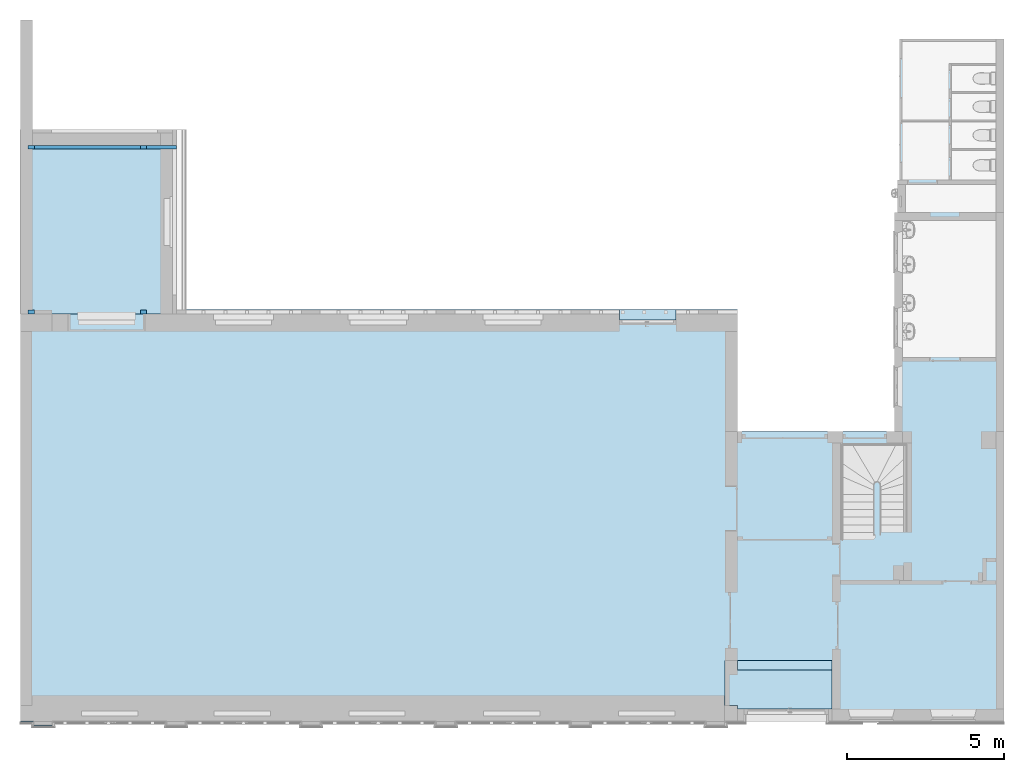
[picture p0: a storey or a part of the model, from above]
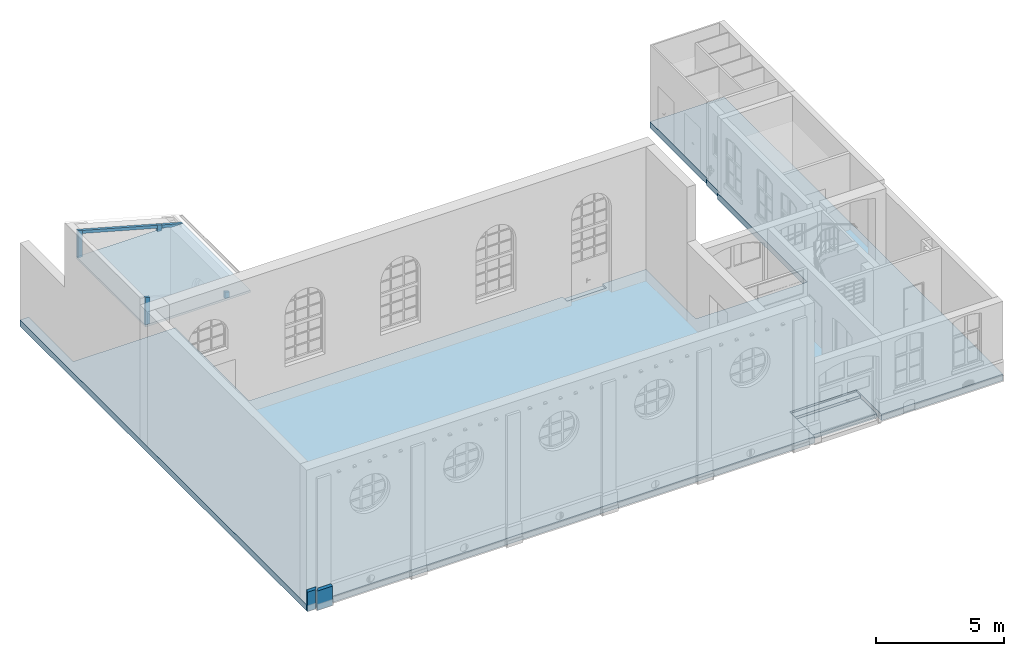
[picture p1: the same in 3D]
Properties of the parts of a building model (IFC4), part 1 of 2

# File
Description: no view
File name: KRD021.ifc
Time: 2026-01-22T15:29:08
Author: AP03
Organization: No Organization
Written by: ODA SDAI 25.4
Authorization: AP03

# IfcSite, Liegenschaft XXXXXXXXX (LuGM-Nr.) (TB 1-99) ANPASSEN !!!
RefLatitude: 48, 8, 10, 320000; RefLongitude: 11, 41, 19, 320000

# IfcBuildingStorey (25)
Name | In | Elevation (m)
Lageplan mit Gebäudebezeichnung und Geodaten (TB 20-24) |  | 0
Landschafts-/Freiflächenplanung (TB 25-29) |  | 0
Ver-/Entsorgungsleitungen mit geobasierten Daten (Daten an FB 62 übermitteln) (TB 30-39) |  | 0
Feuerwehrpläne (TB 40-49) |  | 0
Brandschutzpläne (TB 50-59) |  | 0
Nachrichten-/Netzwerktechnik (TB 60-69) |  | 0
Gefahrenmeldeanlagen (TB 70-79) |  | 0
Flucht-/Rettungswegpläne (TB 80-84) |  | 0
Geb. A Fundamentplan (TB 100-102) | Bestandsgebäude A - Sporthalle / Wohnhaus (TB 100-499) ANPASSEN !!! | 0
Geb. A 1. Untergeschoss (TB 150-199) | Bestandsgebäude A - Sporthalle / Wohnhaus (TB 100-499) ANPASSEN !!! | -2.4
Architektur (TB 150-159) | Geb. A 1. Untergeschoss (TB 150-199)
TGA (TB 160-194) | Geb. A 1. Untergeschoss (TB 150-199)
Brandschutz (TB 195-199) | Geb. A 1. Untergeschoss (TB 150-199)
Geb. A Erdgeschoss (TB 200-249) | Bestandsgebäude A - Sporthalle / Wohnhaus (TB 100-499) ANPASSEN !!! | 0
Architektur (TB 200-209) | Geb. A Erdgeschoss (TB 200-249)
TGA (TB 210-244) | Geb. A Erdgeschoss (TB 200-249)
Brandschutz (TB 245-249) | Geb. A Erdgeschoss (TB 200-249)
Geb. A 1. Obergeschoss (TB 250-299) | Bestandsgebäude A - Sporthalle / Wohnhaus (TB 100-499) ANPASSEN !!! | 3.87
Architektur (TB 250-259) | Geb. A 1. Obergeschoss (TB 250-299)
TGA (TB 260-294) | Geb. A 1. Obergeschoss (TB 250-299)
Brandschutz (TB 295-299) | Geb. A 1. Obergeschoss (TB 250-299)
Geb. A Dachgeschoss (TB 450-499) | Bestandsgebäude A - Sporthalle / Wohnhaus (TB 100-499) ANPASSEN !!! | 7.71
Architektur (TB 450-459) | Geb. A Dachgeschoss (TB 450-499)
TGA (TB 460-494) | Geb. A Dachgeschoss (TB 450-499)
Brandschutz (TB 495-499) | Geb. A Dachgeschoss (TB 450-499)

# IfcSpace (21)
LongName: EG
AllplanAttributes - Raumumschließung: R; Flächenart_DIN277: N; Flächenart_Wohnfläche: WO; BauNVO_Anrechnung_auf_GR: 0; Nutzungsart_Din277: USA; BauNVO_Anrechnung_auf_GF: 0; Raum unter Treppe (Wohnfl erst ab 2m): 0; Faktor_Wohnfläche_Raum: 1; Faktor_DIN277: 1; Abrechnungsart: m²; Objektname: Raum
Pset_SpaceCommon - IsExternal: no; HandicapAccessible: no; GrossPlannedArea: 0 m2; NetPlannedArea: 0 m2; PubliclyAccessible: yes
Name | In | Ortscode_Geschoßbezeichnung | Allright_Bauteil_ID
TURNHALLE | Architektur (TB 200-209) | E.02 | 0208Rau0000000012
GERÄTE-R. | Architektur (TB 200-209) | E.01 | 0208Rau0000000137
FLUR | Architektur (TB 200-209) | E.04 | 0208Rau0000000301
UMKLEIDE-R.3 | Architektur (TB 200-209) | E.03 | 0208Rau0000000314
UMKLEIDE-R.1 | Architektur (TB 200-209) | E.05 | 0208Rau0000000262
UMKLEIDE-R.2 | Architektur (TB 200-209) | E.07 | 0208Rau0000000239
WASCHR. | Architektur (TB 200-209) | E.08 | 0208Rau0000000150
ABSTELL-R. | Architektur (TB 200-209) | E.09 | 0208Rau0000000203
MÄDCHEN | Architektur (TB 200-209) | E.10 | 0208Rau0000000176
KNABEN | Architektur (TB 200-209) | E.11 | 0208Rau0000000163
TREPPEN | Architektur (TB 200-209) | E.06 | 0208Rau0000000252
TURNHALLE | Architektur (TB 250-259) | OG.01 | 0257Rau0000000002
FLUR | Architektur (TB 250-259) | OG.03 | 0257Rau0000000028
UMKLEIDE-R.3 | Architektur (TB 250-259) | OG.02 | 0257Rau0000000015
ZIMMER | Architektur (TB 250-259) | OG.07 | 0257Rau0000000093
UMKLEIDE-R.2 | Architektur (TB 250-259) | OG.06 | 0257Rau0000000054
UMKLEIDE-R.1 | Architektur (TB 250-259) | OG.04 | 0257Rau0000000041
TREPPEN | Architektur (TB 250-259) | OG.05 | 0257Rau0000000080
KAMMER | Architektur (TB 450-459) | D.03 | 0455Rau0000000026
TREPPEN | Architektur (TB 450-459) | D.02 | 0455Rau0000000023
TURNHALLE | Architektur (TB 450-459) | D.01 | 0455Rau0000000020

# IfcBeam (53)
Pset_BeamCommon - Status: NEW
Name | In | PredefinedType | Schichtnummer | Allright_Bauteil_ID | Abrechnungsart | Objektname
 | Architektur (TB 200-209) | BEAM | 1 | 0204Hbt0000000005 | m | Stahl-, Holzbauteil allgemein
 | Architektur (TB 250-259) | BEAM | 1 | 0254Hbt0000001016 | m | Stahl-, Holzbauteil allgemein
 | Architektur (TB 250-259) | BEAM | 1 | 0254Hbt0000001018 | m | Stahl-, Holzbauteil allgemein
 | Architektur (TB 250-259) | BEAM | 1 | 0254Hbt0000001020 | m | Stahl-, Holzbauteil allgemein
 | Architektur (TB 250-259) | BEAM | 1 | 0254Hbt0000001024 | m | Stahl-, Holzbauteil allgemein
 | Architektur (TB 250-259) | BEAM | 1 | 0254Hbt0000001026 | m | Stahl-, Holzbauteil allgemein
 | Architektur (TB 250-259) | BEAM | 1 | 0254Hbt0000001032 | m | Stahl-, Holzbauteil allgemein
 | Architektur (TB 250-259) | BEAM | 1 | 0254Hbt0000001034 | m | Stahl-, Holzbauteil allgemein
 | Architektur (TB 250-259) | BEAM | 1 | 0254Hbt0000001039 | m | Stahl-, Holzbauteil allgemein
 | Architektur (TB 250-259) | BEAM | 1 | 0254Hbt0000001040 | m | Stahl-, Holzbauteil allgemein
 | Architektur (TB 250-259) | BEAM | 1 | 0254Hbt0000001045 | m | Stahl-, Holzbauteil allgemein
 | Architektur (TB 250-259) | BEAM | 1 | 0254Hbt0000001046 | m | Stahl-, Holzbauteil allgemein
 | Architektur (TB 250-259) | BEAM | 1 | 0254Hbt0000001051 | m | Stahl-, Holzbauteil allgemein
 | Architektur (TB 250-259) | BEAM | 1 | 0254Hbt0000001052 | m | Stahl-, Holzbauteil allgemein
 | Architektur (TB 250-259) | BEAM | 1 | 0254Hbt0000001057 | m | Stahl-, Holzbauteil allgemein
 | Architektur (TB 250-259) | BEAM | 1 | 0254Hbt0000001058 | m | Stahl-, Holzbauteil allgemein
 | Architektur (TB 250-259) | BEAM | 1 | 0254Hbt0000001064 | m | Stahl-, Holzbauteil allgemein
 | Architektur (TB 250-259) | BEAM | 1 | 0254Hbt0000001066 | m | Stahl-, Holzbauteil allgemein
 | Architektur (TB 250-259) | BEAM | 1 | 0254Hbt0000001069 | m | Stahl-, Holzbauteil allgemein
 | Architektur (TB 250-259) | BEAM | 1 | 0254Hbt0000001190 | m | Stahl-, Holzbauteil allgemein
 | Architektur (TB 250-259) | BEAM | 1 | 0254Hbt0000001193 | m | Stahl-, Holzbauteil allgemein
 | Architektur (TB 250-259) | BEAM | 1 | 0254Hbt0000001196 | m | Stahl-, Holzbauteil allgemein
 | Architektur (TB 250-259) | BEAM | 1 | 0254Hbt0000001199 | m | Stahl-, Holzbauteil allgemein
 | Architektur (TB 250-259) | BEAM | 1 | 0254Hbt0000001202 | m | Stahl-, Holzbauteil allgemein
 | Architektur (TB 250-259) | BEAM | 1 | 0254Hbt0000001205 | m | Stahl-, Holzbauteil allgemein
 | Architektur (TB 250-259) |  |  | 0254Unz0000001071 | m³ | Unterzug | AllplanAttributes - 2D Interaktion: yes; Pset_BeamCommon - IsExternal: no; Slope: 0 deg; ThermalTransmittance: 0 W/K/m2; Roll: 0 deg
 | Architektur (TB 250-259) |  |  | 0254Unz0000001077 | m³ | Unterzug | AllplanAttributes - 2D Interaktion: yes; Pset_BeamCommon - IsExternal: no; Slope: 0 deg; ThermalTransmittance: 0 W/K/m2; Roll: 0 deg
 | Architektur (TB 250-259) |  |  | 0254Unz0000001340 | m³ | Unterzug | AllplanAttributes - 2D Interaktion: yes; Pset_BeamCommon - IsExternal: no; Slope: 0 deg; ThermalTransmittance: 0 W/K/m2; Roll: 0 deg
 | Architektur (TB 250-259) |  |  | 0254Unz0000001337 | m³ | Unterzug | AllplanAttributes - 2D Interaktion: yes; Pset_BeamCommon - IsExternal: no; Slope: 0 deg; ThermalTransmittance: 0 W/K/m2; Roll: 0 deg
 | Architektur (TB 250-259) |  |  | 0254Unz0000001075 | m³ | Unterzug | AllplanAttributes - 2D Interaktion: yes; Pset_BeamCommon - IsExternal: no; Slope: 0 deg; ThermalTransmittance: 0 W/K/m2; Roll: 0 deg
 | Architektur (TB 250-259) |  |  | 0254Unz0000001081 | m³ | Unterzug | AllplanAttributes - 2D Interaktion: yes; Pset_BeamCommon - IsExternal: no; Slope: 0 deg; ThermalTransmittance: 0 W/K/m2; Roll: 0 deg
 | Architektur (TB 250-259) |  |  | 0254Unz0000001111 | m³ | Unterzug | AllplanAttributes - 2D Interaktion: yes; Pset_BeamCommon - IsExternal: no; Slope: 0 deg; ThermalTransmittance: 0 W/K/m2; Roll: 0 deg
 | Architektur (TB 250-259) |  |  | 0254Unz0000001086 | m³ | Unterzug | AllplanAttributes - 2D Interaktion: yes; Pset_BeamCommon - IsExternal: no; Slope: 0 deg; ThermalTransmittance: 0 W/K/m2; Roll: 0 deg
 | Architektur (TB 250-259) |  |  | 0254Unz0000001093 | m³ | Unterzug | AllplanAttributes - 2D Interaktion: yes; Pset_BeamCommon - IsExternal: no; Slope: 0 deg; ThermalTransmittance: 0 W/K/m2; Roll: 0 deg
 | Architektur (TB 250-259) |  |  | 0254Unz0000001100 | m³ | Unterzug | AllplanAttributes - 2D Interaktion: yes; Pset_BeamCommon - IsExternal: no; Slope: 0 deg; ThermalTransmittance: 0 W/K/m2; Roll: 0 deg
 | Architektur (TB 250-259) |  |  | 0254Unz0000001119 | m³ | Unterzug | AllplanAttributes - 2D Interaktion: yes; Pset_BeamCommon - IsExternal: no; Slope: 0 deg; ThermalTransmittance: 0 W/K/m2; Roll: 0 deg
 | Architektur (TB 250-259) |  |  | 0254Unz0000001123 | m³ | Unterzug | AllplanAttributes - 2D Interaktion: yes; Pset_BeamCommon - IsExternal: no; Slope: 0 deg; ThermalTransmittance: 0 W/K/m2; Roll: 0 deg
 | Architektur (TB 250-259) |  |  | 0254Unz0000001134 | m³ | Unterzug | AllplanAttributes - 2D Interaktion: yes; Pset_BeamCommon - IsExternal: no; Slope: 0 deg; ThermalTransmittance: 0 W/K/m2; Roll: 0 deg
 | Architektur (TB 250-259) |  |  | 0254Unz0000001136 | m³ | Unterzug | AllplanAttributes - 2D Interaktion: yes; Pset_BeamCommon - IsExternal: no; Slope: 0 deg; ThermalTransmittance: 0 W/K/m2; Roll: 0 deg
 | Architektur (TB 450-459) | BEAM | 1 | 0453Hbt0000000005 | m | Stahl-, Holzbauteil allgemein
 | Architektur (TB 450-459) | BEAM | 1 | 0453Hbt0000000008 | m | Stahl-, Holzbauteil allgemein
 | Architektur (TB 450-459) | BEAM | 1 | 0453Hbt0000000012 | m | Stahl-, Holzbauteil allgemein
 | Architektur (TB 450-459) | BEAM | 1 | 0453Hbt0000000028 | m | Stahl-, Holzbauteil allgemein
 | Architektur (TB 450-459) | BEAM | 1 | 0453Hbt0000000030 | m | Stahl-, Holzbauteil allgemein
 | Architektur (TB 450-459) | BEAM | 1 | 0453Hbt0000000034 | m | Stahl-, Holzbauteil allgemein
 | Architektur (TB 450-459) | BEAM | 1 | 0453Hbt0000000040 | m | Stahl-, Holzbauteil allgemein
 | Architektur (TB 450-459) | BEAM | 1 | 0453Hbt0000000047 | m | Stahl-, Holzbauteil allgemein
 | Architektur (TB 450-459) | BEAM | 1 | 0453Hbt0000000050 | m | Stahl-, Holzbauteil allgemein
 | Architektur (TB 450-459) |  |  | 0453Unz0000000043 | m³ | Unterzug | AllplanAttributes - 2D Interaktion: yes; Pset_BeamCommon - IsExternal: no; Slope: 0 deg; ThermalTransmittance: 0 W/K/m2; Roll: 0 deg
 | Architektur (TB 450-459) |  |  | 0453Unz0000000017 | m³ | Unterzug | AllplanAttributes - 2D Interaktion: yes; Pset_BeamCommon - IsExternal: no; Slope: 0 deg; ThermalTransmittance: 0 W/K/m2; Roll: 0 deg
 | Architektur (TB 450-459) |  |  | 0453Unz0000000036 | m³ | Unterzug | AllplanAttributes - 2D Interaktion: yes; Pset_BeamCommon - IsExternal: no; Slope: 0 deg; ThermalTransmittance: 0 W/K/m2; Roll: 0 deg
 | Architektur (TB 450-459) |  |  | 0453Unz0000000024 | m³ | Unterzug | AllplanAttributes - 2D Interaktion: yes; Pset_BeamCommon - IsExternal: no; Slope: 0 deg; ThermalTransmittance: 0 W/K/m2; Roll: 0 deg
 | Architektur (TB 450-459) |  |  | 0453Unz0000000019 | m³ | Unterzug | AllplanAttributes - 2D Interaktion: yes; Pset_BeamCommon - IsExternal: no; Slope: 0 deg; ThermalTransmittance: 0 W/K/m2; Roll: 0 deg

# IfcBuildingElementProxy (192)
Name | In
47 x  | Architektur (TB 200-209)
Gutter | Architektur (TB 200-209) | AllplanAttributes - UK: 0 m; OK: 0 m; Einheit: Stck; Stück: 1; V6: 0 m; V7: 0 m; V8: 0 m; V9: 0; Länge: 5.76 m; Programmversion: 1.0; Text1: Main part: 5.760m; Text2: Style: Half-round, outside, Cross-sectional size: 280mm; Text3: Extension: 0.660m; Text5: Cover on the left: Available , Cover on the right: Available; Bezeichnung: Gutter; Plugin_Bezeichnung: MainObject; Plugin_Objektname: SmartPartCompressed; Version: 1.0; Allright_Bauteil_ID: 0202Sma0000000014; Abrechnungsart: St; Objektname: SmartPart
WC, standing, with reservoir | Architektur (TB 200-209) | AllplanAttributes - UK: 0 m; OK: 0 m; V6: 0 m; V7: 0 m; V8: 0 m; V9: 0; Bezeichnung: WC, standing, with reservoir; Allright_Bauteil_ID: 0207Mak0000000005; Abrechnungsart: St; Objektname: Makro
WC, standing, with reservoir | Architektur (TB 200-209) | AllplanAttributes - UK: 0 m; OK: 0 m; V6: 0 m; V7: 0 m; V8: 0 m; V9: 0; Bezeichnung: WC, standing, with reservoir; Allright_Bauteil_ID: 0207Mak0000000006; Abrechnungsart: St; Objektname: Makro
WC, standing, with reservoir | Architektur (TB 200-209) | AllplanAttributes - UK: 0 m; OK: 0 m; V6: 0 m; V7: 0 m; V8: 0 m; V9: 0; Bezeichnung: WC, standing, with reservoir; Allright_Bauteil_ID: 0207Mak0000000004; Abrechnungsart: St; Objektname: Makro
WC, standing, with reservoir | Architektur (TB 200-209) | AllplanAttributes - UK: 0 m; OK: 0 m; V6: 0 m; V7: 0 m; V8: 0 m; V9: 0; Bezeichnung: WC, standing, with reservoir; Allright_Bauteil_ID: 0207Mak0000000003; Abrechnungsart: St; Objektname: Makro
Wash-basin 36.5 | Architektur (TB 200-209) | AllplanAttributes - UK: 0.8 m; OK: 0 m; V6: 0 m; V7: 0 m; V8: 0 m; V9: 0; Bezeichnung: Wash-basin 36.5; Allright_Bauteil_ID: 0207Mak0000000031; Abrechnungsart: St; Objektname: Makro
Wash-basin 36.5 | Architektur (TB 200-209) | AllplanAttributes - UK: 0.8 m; OK: 0 m; V6: 0 m; V7: 0 m; V8: 0 m; V9: 0; Bezeichnung: Wash-basin 36.5; Allright_Bauteil_ID: 0207Mak0000000029; Abrechnungsart: St; Objektname: Makro
Wash-basin 36.5 | Architektur (TB 200-209) | AllplanAttributes - UK: 0.8 m; OK: 0 m; V6: 0 m; V7: 0 m; V8: 0 m; V9: 0; Bezeichnung: Wash-basin 36.5; Allright_Bauteil_ID: 0207Mak0000000027; Abrechnungsart: St; Objektname: Makro
Wash-basin 36.5 | Architektur (TB 200-209) | AllplanAttributes - UK: 0.8 m; OK: 0 m; V6: 0 m; V7: 0 m; V8: 0 m; V9: 0; Bezeichnung: Wash-basin 36.5; Allright_Bauteil_ID: 0207Mak0000000019; Abrechnungsart: St; Objektname: Makro
Wash-basin 36.5 | Architektur (TB 200-209) | AllplanAttributes - UK: 0.8 m; OK: 0 m; V6: 0 m; V7: 0 m; V8: 0 m; V9: 0; Bezeichnung: Wash-basin 36.5; Allright_Bauteil_ID: 0207Mak0000000011; Abrechnungsart: St; Objektname: Makro
87 x  | Architektur (TB 250-259)
Gutter | Architektur (TB 250-259) | AllplanAttributes - UK: 0 m; OK: 0 m; Einheit: Stck; Stück: 1; V6: 0 m; V7: 0 m; V8: 0 m; V9: 0; Länge: 22.47 m; Programmversion: 1.0; Text1: Main part: 22.470m; Text2: Style: Half-round, outside, Cross-sectional size: 280mm; Text3: Extension: 1.000m; Text5: Cover on the left: Available , Cover on the right: Available; Bezeichnung: Gutter; Plugin_Bezeichnung: MainObject; Plugin_Objektname: SmartPartCompressed; Version: 1.0; Allright_Bauteil_ID: 0252Sma0000000040; Abrechnungsart: St; Objektname: SmartPart
Gutter | Architektur (TB 250-259) | AllplanAttributes - UK: 0 m; OK: 0 m; Einheit: Stck; Stück: 1; V6: 0 m; V7: 0 m; V8: 0 m; V9: 0; Länge: 22.87 m; Programmversion: 1.0; Text1: Main part: 22.870m; Text2: Style: Half-round, outside, Cross-sectional size: 280mm; Text3: Extension: 1.000m; Text5: Cover on the left: Available , Cover on the right: Available; Bezeichnung: Gutter; Plugin_Bezeichnung: MainObject; Plugin_Objektname: SmartPartCompressed; Version: 1.0; Allright_Bauteil_ID: 0252Sma0000000042; Abrechnungsart: St; Objektname: SmartPart
Gutter | Architektur (TB 250-259) | AllplanAttributes - UK: 0 m; OK: 0 m; Einheit: Stck; Stück: 1; V6: 0 m; V7: 0 m; V8: 0 m; V9: 0; Länge: 6.19 m; Programmversion: 1.0; Text1: Main part: 6.190m; Text2: Style: Half-round, outside, Cross-sectional size: 280mm; Text3: Extension: 0.660m; Text5: Cover on the left: Available , Cover on the right: Available; Bezeichnung: Gutter; Plugin_Bezeichnung: MainObject; Plugin_Objektname: SmartPartCompressed; Version: 1.0; Allright_Bauteil_ID: 0253Sma0000006198; Abrechnungsart: St; Objektname: SmartPart
43 x  | Architektur (TB 450-459)
Gutter | Architektur (TB 450-459) | AllplanAttributes - UK: 0 m; OK: 0 m; Einheit: Stck; Stück: 1; V6: 0 m; V7: 0 m; V8: 0 m; V9: 0; Länge: 8.9 m; Programmversion: 1.0; Text1: Main part: 8.900m; Text2: Style: Half-round, outside, Cross-sectional size: 280mm; Text3: Extension: 0.660m; Text5: Cover on the left: Available , Cover on the right: Available; Bezeichnung: Gutter; Plugin_Bezeichnung: MainObject; Plugin_Objektname: SmartPartCompressed; Version: 1.0; Allright_Bauteil_ID: 0450Sma0000038216; Abrechnungsart: St; Objektname: SmartPart
Gutter | Architektur (TB 450-459) | AllplanAttributes - UK: 0 m; OK: 0 m; Einheit: Stck; Stück: 1; V6: 0 m; V7: 0 m; V8: 0 m; V9: 0; Länge: 8.24 m; Programmversion: 1.0; Text1: Main part: 8.240m; Text2: Style: Half-round, outside, Cross-sectional size: 280mm; Text3: Extension: 0.660m; Text5: Cover on the left: Available , Cover on the right: Available; Bezeichnung: Gutter; Plugin_Bezeichnung: MainObject; Plugin_Objektname: SmartPartCompressed; Version: 1.0; Allright_Bauteil_ID: 0450Sma0000038220; Abrechnungsart: St; Objektname: SmartPart

# IfcColumn (16)
PredefinedType: COLUMN
AllplanAttributes - 2D Interaktion: yes; Abrechnungsart: m; Objektname: Stütze
Pset_ColumnCommon - Status: NEW; IsExternal: no; Slope: 0 deg; ThermalTransmittance: 0 W/K/m2; Roll: 0 deg
Name | In | Allright_Bauteil_ID
 | Architektur (TB 200-209) | 0205St 0000000726
 | Architektur (TB 200-209) | 0205St 0000000739
 | Architektur (TB 200-209) | 0205St 0000000729
 | Architektur (TB 200-209) | 0205St 0000000704
 | Architektur (TB 250-259) | 0255St 0000001204
 | Architektur (TB 250-259) | 0255St 0000001201
 | Architektur (TB 250-259) | 0255St 0000001199
 | Architektur (TB 250-259) | 0255St 0000001197
 | Architektur (TB 250-259) | 0255St 0000001195
 | Architektur (TB 250-259) | 0255St 0000001193
 | Architektur (TB 250-259) | 0255St 0000001191
 | Architektur (TB 250-259) | 0255St 0000001188
 | Architektur (TB 450-459) | 0454St 0000000931
 | Architektur (TB 450-459) | 0454St 0000000933
 | Architektur (TB 450-459) | 0454St 0000000928
 | Architektur (TB 450-459) | 0454St 0000000987

# IfcCovering (8)
In: Architektur (TB 200-209)
PredefinedType: CEILING; Material: layer 0.03 m
AllplanAttributes - Object Layer Attributes #1, Schichtnummer: 1; Object Layer Attributes #1, Schichtdicke: 0.03 m; Object Layer Attributes #1, Dicke: 0 m; Object Layer Attributes #1, Faktor: 1; Object Layer Attributes #1, Bezugshöhe: 0; Object Layer Attributes #1, Deltahöhe: 0; Object Layer Attributes #1, Abrechnungsart: m²; Object Layer Attributes #1, Objektname: Deckenfläche
Pset_CoveringCommon - Status: NEW; IsExternal: no; ThermalTransmittance: 0 W/K/m2; Combustible: no
Name | Object Layer Attributes #1, Allright_Bauteil_ID
 | 0203Dfl0000000017/01
 | 0203Dfl0000000015/01
 | 0203Dfl0000000013/01
 | 0203Dfl0000000011/01
 | 0203Dfl0000000002/01
 | 0203Dfl0000000005/01
 | 0203Dfl0000000007/01
 | 0203Dfl0000000009/01

# IfcDoor (8)
PredefinedType: DOOR; OperationType: USERDEFINED
AllplanAttributes (door) - V6: 0 m; V7: 0 m; V8: 0 m; V9: 0; Programmversion: 3.0; Bezeichnung: door; Plugin_Bezeichnung: MainObject; Plugin_Objektname: SmartPartCompressed; Glasanteil_berücksichtigen: 100; Version: 7.0; Öffnungszweck: -; ProtectedOpening: no; Attributset-Objekt: Door; Abrechnungsart: St; Objektname: Türmakro, -SmartPart
AllplanQuantities - HeightWindowSillOutside: 0; HeightWindowSillInside: 0; OffsetOpeningBottom: 0; OffsetOpeningTop: 0; OffsetOpeningLeft: 0; OffsetOpeningRight: 0
Pset_DoorCommon - Status: NEW; IsExternal: yes; ThermalTransmittance: 0 W/K/m2; HandicapAccessible: no; SmokeStop: no; SelfClosing: no; FireExit: no; Infiltration: 0 m3/hour/m; HasDrive: yes; WaterTightnessRating: -; MechanicalLoadRating: -; WindLoadRating: -
Pset_DoorWindowGlazingType - Shading Coefficient: 0
Pset_ManufacturerTypeInformation - ModelReference: 0.000000; ProductionYear: 0
Name | In | OverallHeight (m) | OverallWidth (m) | Allright_Bauteil_ID | GlassSurface | DeductionOpeningBottom | DeductionOpeningLeft = DeductionOpeningRight | DeductionOpeningTop
door | Architektur (TB 200-209) | 5 | 1.8 | 0200Mak0000041408 | 3.94475 | 50 | 80 | 80
door | Architektur (TB 200-209) | 2.35 | 1.77 | 0200Mak0000031209 | 2.90839 | 0 | 100 | 100
door | Architektur (TB 200-209) | 3.47 | 3.02 | 0200Mak0000043909 | 2.6818 | 0 | 170 | 40
door | Architektur (TB 200-209) | 2.38 | 1.5 | 0200Mak0000054528 | 2.36902 | 0 | 100 | 100
door | Architektur (TB 200-209) | 3.18 | 2.72 | 0200Mak0000144874 | 1.95475 | 0 | 100 | 100
door | Architektur (TB 200-209) | 3.33 | 2.71 | 0200Mak0000137546 | 1.65419 | 100 | 120 | 120
door | Architektur (TB 250-259) | 3.47 | 3.02 | 0250Mak0000009697 | 2.9748 | 0 | 170 | 40
door | Architektur (TB 250-259) | 3.47 | 1.68 | 0250Mak0000009707 | 1.3869 | 0 | 120 | 40

# IfcDoor: 1l white blockframe
In: Architektur (TB 200-209)
Type - PredefinedType: DOOR; OperationType: SINGLE_SWING_LEFT; ParameterTakesPrecedence: no
Type - IfcDoorLiningProperties - LiningDepth: 0.15 m; LiningThickness: 0.08 m
OverallHeight: 3.25 m; OverallWidth: 1.39 m
AllplanAttributes (1l white blockframe) - V6: 0 m; V7: 0 m; V8: 0 m; V9: 0; Programmversion: 3.0; Bezeichnung: 1l white blockframe; Plugin_Bezeichnung: MainObject; Plugin_Objektname: SmartPartCompressed; Glasanteil_berücksichtigen: 0; Version: 8.0; Attributset-Objekt: Door; Allright_Bauteil_ID: 0200Mak0000144876; Abrechnungsart: St; Objektname: Türmakro, -SmartPart
AllplanQuantities - GlassSurface: 1.12166; HeightWindowSillOutside: 0; HeightWindowSillInside: 0; OffsetOpeningBottom: 0; OffsetOpeningTop: 0; OffsetOpeningLeft: 0; OffsetOpeningRight: 0; DeductionOpeningBottom: 0; DeductionOpeningLeft: 80; DeductionOpeningRight: 80; DeductionOpeningTop: 80
Pset_DoorCommon - Status: NEW; IsExternal: no; ThermalTransmittance: 0 W/K/m2; HandicapAccessible: no; SmokeStop: no; SelfClosing: no; FireExit: no; Infiltration: 0 m3/hour/m; HasDrive: yes

# IfcDoor: Door
In: Architektur (TB 200-209)
Type - PredefinedType: DOOR; OperationType: DOUBLE_DOOR_SINGLE_SWING; ParameterTakesPrecedence: no
Type - IfcDoorLiningProperties - LiningDepth: 0.56 m; LiningThickness: 0.07 m
OverallHeight: 2.76 m; OverallWidth: 2.45 m
AllplanAttributes (Door) - V6: 0 m; V7: 0 m; V8: 0 m; V9: 0; Programmversion: 3.0; Bezeichnung: Door; Plugin_Bezeichnung: MainObject; Plugin_Objektname: SmartPartCompressed; Glasanteil_berücksichtigen: 0; Version: 8.0; Attributset-Objekt: Door; Allright_Bauteil_ID: 0200Mak0000042538; Abrechnungsart: St; Objektname: Türmakro, -SmartPart
AllplanQuantities - GlassSurface: 0; HeightWindowSillOutside: 0; HeightWindowSillInside: 0; OffsetOpeningBottom: 0; OffsetOpeningTop: 0; OffsetOpeningLeft: 0; OffsetOpeningRight: 0; DeductionOpeningBottom: 0; DeductionOpeningLeft: 70; DeductionOpeningRight: 70; DeductionOpeningTop: 70
Pset_DoorCommon - Status: NEW; IsExternal: no; ThermalTransmittance: 0 W/K/m2; HandicapAccessible: no; SmokeStop: no; SelfClosing: no; FireExit: no; Infiltration: 0 m3/hour/m; HasDrive: yes

# IfcDoor: door (2)
In: Architektur (TB 200-209)
Type - PredefinedType: DOOR; OperationType: DOUBLE_DOOR_SINGLE_SWING; ParameterTakesPrecedence: no
Type - IfcDoorLiningProperties - LiningDepth: 0.08 m; LiningThickness: 0.03 m
OverallHeight: 2.06 m; OverallWidth: 1.26 m
AllplanAttributes (door) - V6: 0 m; V7: 0 m; V8: 0 m; V9: 0; Programmversion: 3.0; Bezeichnung: door; Plugin_Bezeichnung: MainObject; Plugin_Objektname: SmartPartCompressed; Glasanteil_berücksichtigen: 100; Version: 7.0; Öffnungszweck: -; ProtectedOpening: no; Attributset-Objekt: Door; Abrechnungsart: St; Objektname: Türmakro, -SmartPart
AllplanQuantities - GlassSurface: 0; HeightWindowSillOutside: 0; HeightWindowSillInside: 0; OffsetOpeningBottom: 0; OffsetOpeningTop: 0; OffsetOpeningLeft: 0; OffsetOpeningRight: 0; DeductionOpeningBottom: 0; DeductionOpeningLeft: 30; DeductionOpeningRight: 30; DeductionOpeningTop: 30
Pset_DoorCommon - Status: NEW; IsExternal: yes; ThermalTransmittance: 0 W/K/m2; HandicapAccessible: no; SmokeStop: no; SelfClosing: no; FireExit: no; Infiltration: 0 m3/hour/m; HasDrive: yes; WaterTightnessRating: -; MechanicalLoadRating: -; WindLoadRating: -
Pset_DoorWindowGlazingType - Shading Coefficient: 0
Pset_ManufacturerTypeInformation - ModelReference: 0.000000; ProductionYear: 0
Name | Allright_Bauteil_ID
door | 0200Mak0000043207
door | 0200Mak0000043640

# IfcDoor: door
In: Architektur (TB 450-459)
Type - PredefinedType: DOOR; OperationType: SINGLE_SWING_LEFT; ParameterTakesPrecedence: no
OverallHeight: 1.87 m; OverallWidth: 1 m
AllplanAttributes (door) - V6: 0 m; V7: 0 m; V8: 0 m; V9: 0; Programmversion: 3.0; Bezeichnung: door; Plugin_Bezeichnung: MainObject; Plugin_Objektname: SmartPartCompressed; Glasanteil_berücksichtigen: 100; Version: 7.0; Öffnungszweck: -; ProtectedOpening: no; Attributset-Objekt: Door; Allright_Bauteil_ID: 0450Mak0000062491; Abrechnungsart: St; Objektname: Türmakro, -SmartPart
AllplanQuantities - GlassSurface: 0; HeightWindowSillOutside: 0; HeightWindowSillInside: 0; OffsetOpeningBottom: 0; OffsetOpeningTop: 0; OffsetOpeningLeft: 0; OffsetOpeningRight: 0; DeductionOpeningBottom: 0; DeductionOpeningLeft: 30; DeductionOpeningRight: 30; DeductionOpeningTop: 50
Pset_DoorCommon - Status: NEW; IsExternal: yes; ThermalTransmittance: 0 W/K/m2; HandicapAccessible: no; SmokeStop: no; SelfClosing: no; FireExit: no; Infiltration: 0 m3/hour/m; HasDrive: yes; WaterTightnessRating: -; MechanicalLoadRating: -; WindLoadRating: -
Pset_DoorWindowGlazingType - Shading Coefficient: 0
Pset_ManufacturerTypeInformation - ModelReference: 0.000000; ProductionYear: 0

# IfcDoor: door
In: Architektur (TB 450-459)
Type - PredefinedType: DOOR; OperationType: SINGLE_SWING_LEFT; ParameterTakesPrecedence: no
Type - IfcDoorLiningProperties - LiningDepth: 0.1 m; LiningThickness: 0.05 m
OverallHeight: 2.2 m; OverallWidth: 1.04 m
AllplanAttributes (door) - V6: 0 m; V7: 0 m; V8: 0 m; V9: 0; Programmversion: 3.0; Bezeichnung: door; Plugin_Bezeichnung: MainObject; Plugin_Objektname: SmartPartCompressed; Glasanteil_berücksichtigen: 100; Version: 7.0; Öffnungszweck: -; ProtectedOpening: no; Attributset-Objekt: Door; Allright_Bauteil_ID: 0450Mak0000062061; Abrechnungsart: St; Objektname: Türmakro, -SmartPart
AllplanQuantities - GlassSurface: 0; HeightWindowSillOutside: 0; HeightWindowSillInside: 0; OffsetOpeningBottom: 0; OffsetOpeningTop: 0; OffsetOpeningLeft: 0; OffsetOpeningRight: 0; DeductionOpeningBottom: 0; DeductionOpeningLeft: 50; DeductionOpeningRight: 50; DeductionOpeningTop: 50
Pset_DoorCommon - Status: NEW; IsExternal: yes; ThermalTransmittance: 0 W/K/m2; HandicapAccessible: no; SmokeStop: no; SelfClosing: no; FireExit: no; Infiltration: 0 m3/hour/m; HasDrive: yes; WaterTightnessRating: -; MechanicalLoadRating: -; WindLoadRating: -
Pset_DoorWindowGlazingType - Shading Coefficient: 0
Pset_ManufacturerTypeInformation - ModelReference: 0.000000; ProductionYear: 0

# IfcDoor: door
In: Architektur (TB 450-459)
Type - PredefinedType: DOOR; OperationType: SINGLE_SWING_LEFT; ParameterTakesPrecedence: no
Type - IfcDoorLiningProperties - LiningDepth: 0.12 m; LiningThickness: 0.05 m
OverallHeight: 1.9 m; OverallWidth: 0.86 m
AllplanAttributes (door) - V6: 0 m; V7: 0 m; V8: 0 m; V9: 0; Programmversion: 3.0; Bezeichnung: door; Plugin_Bezeichnung: MainObject; Plugin_Objektname: SmartPartCompressed; Glasanteil_berücksichtigen: 100; Version: 7.0; Öffnungszweck: -; ProtectedOpening: no; Attributset-Objekt: Door; Allright_Bauteil_ID: 0450Mak0000016311; Abrechnungsart: St; Objektname: Türmakro, -SmartPart
AllplanQuantities - GlassSurface: 0; HeightWindowSillOutside: 0; HeightWindowSillInside: 0; OffsetOpeningBottom: 0; OffsetOpeningTop: 0; OffsetOpeningLeft: 0; OffsetOpeningRight: 0; DeductionOpeningBottom: 0; DeductionOpeningLeft: 50; DeductionOpeningRight: 50; DeductionOpeningTop: 50
Pset_DoorCommon - Status: NEW; IsExternal: yes; ThermalTransmittance: 0 W/K/m2; HandicapAccessible: no; SmokeStop: no; SelfClosing: no; FireExit: no; Infiltration: 0 m3/hour/m; HasDrive: yes; WaterTightnessRating: -; MechanicalLoadRating: -; WindLoadRating: -
Pset_DoorWindowGlazingType - Shading Coefficient: 0
Pset_ManufacturerTypeInformation - ModelReference: 0.000000; ProductionYear: 0

# IfcDoor: door
In: Architektur (TB 200-209)
Type - PredefinedType: DOOR; OperationType: SINGLE_SWING_LEFT; ParameterTakesPrecedence: no
Type - IfcDoorLiningProperties - LiningDepth: 0.13 m; LiningThickness: 0.05 m
OverallHeight: 2.35 m; OverallWidth: 1 m
AllplanAttributes (door) - V6: 0 m; V7: 0 m; V8: 0 m; V9: 0; Programmversion: 3.0; Bezeichnung: door; Plugin_Bezeichnung: MainObject; Plugin_Objektname: SmartPartCompressed; Glasanteil_berücksichtigen: 100; Version: 7.0; Öffnungszweck: -; ProtectedOpening: no; Attributset-Objekt: Door; Allright_Bauteil_ID: 0200Mak0000036180; Abrechnungsart: St; Objektname: Türmakro, -SmartPart
AllplanQuantities - GlassSurface: 0; HeightWindowSillOutside: 0; HeightWindowSillInside: 0; OffsetOpeningBottom: 0; OffsetOpeningTop: 0; OffsetOpeningLeft: 0; OffsetOpeningRight: 0; DeductionOpeningBottom: 0; DeductionOpeningLeft: 50; DeductionOpeningRight: 50; DeductionOpeningTop: 50
Pset_DoorCommon - Status: NEW; IsExternal: yes; ThermalTransmittance: 0 W/K/m2; HandicapAccessible: no; SmokeStop: no; SelfClosing: no; FireExit: no; Infiltration: 0 m3/hour/m; HasDrive: yes; WaterTightnessRating: -; MechanicalLoadRating: -; WindLoadRating: -
Pset_DoorWindowGlazingType - Shading Coefficient: 0
Pset_ManufacturerTypeInformation - ModelReference: 0.000000; ProductionYear: 0

# IfcDoor: door (4)
In: Architektur (TB 200-209)
Type - PredefinedType: DOOR; OperationType: SINGLE_SWING_RIGHT; ParameterTakesPrecedence: no
Type - IfcDoorLiningProperties - LiningDepth: 0.08 m; LiningThickness: 0.02 m
OverallHeight: 2.2 m; OverallWidth: 0.6 m
AllplanAttributes (door) - V6: 0 m; V7: 0 m; V8: 0 m; V9: 0; Programmversion: 3.0; Bezeichnung: door; Plugin_Bezeichnung: MainObject; Plugin_Objektname: SmartPartCompressed; Glasanteil_berücksichtigen: 100; Version: 7.0; Öffnungszweck: -; ProtectedOpening: no; Attributset-Objekt: Door; Abrechnungsart: St; Objektname: Türmakro, -SmartPart
AllplanQuantities - GlassSurface: 0; HeightWindowSillOutside: 0; HeightWindowSillInside: 0; OffsetOpeningBottom: 0; OffsetOpeningTop: 0; OffsetOpeningLeft: 0; OffsetOpeningRight: 0; DeductionOpeningBottom: 0; DeductionOpeningLeft: 20; DeductionOpeningRight: 20; DeductionOpeningTop: 20
Pset_DoorCommon - Status: NEW; IsExternal: yes; ThermalTransmittance: 0 W/K/m2; HandicapAccessible: no; SmokeStop: no; SelfClosing: no; FireExit: no; Infiltration: 0 m3/hour/m; HasDrive: yes; WaterTightnessRating: -; MechanicalLoadRating: -; WindLoadRating: -
Pset_DoorWindowGlazingType - Shading Coefficient: 0
Pset_ManufacturerTypeInformation - ModelReference: 0.000000; ProductionYear: 0
Name | Allright_Bauteil_ID
door | 0200Mak0000040340
door | 0200Mak0000040328
door | 0200Mak0000040316
door | 0200Mak0000040100

# IfcDoor: door (3)
Type - PredefinedType: DOOR; OperationType: SINGLE_SWING_RIGHT; ParameterTakesPrecedence: no
Type - IfcDoorLiningProperties - LiningDepth: 0.13 m; LiningThickness: 0.05 m
AllplanAttributes (door) - V6: 0 m; V7: 0 m; V8: 0 m; V9: 0; Programmversion: 3.0; Bezeichnung: door; Plugin_Bezeichnung: MainObject; Plugin_Objektname: SmartPartCompressed; Glasanteil_berücksichtigen: 100; Version: 7.0; Öffnungszweck: -; ProtectedOpening: no; Attributset-Objekt: Door; Abrechnungsart: St; Objektname: Türmakro, -SmartPart
AllplanQuantities - GlassSurface: 0; HeightWindowSillOutside: 0; HeightWindowSillInside: 0; OffsetOpeningBottom: 0; OffsetOpeningTop: 0; OffsetOpeningLeft: 0; OffsetOpeningRight: 0; DeductionOpeningBottom: 0; DeductionOpeningLeft: 50; DeductionOpeningRight: 50; DeductionOpeningTop: 50
Pset_DoorCommon - Status: NEW; IsExternal: yes; ThermalTransmittance: 0 W/K/m2; HandicapAccessible: no; SmokeStop: no; SelfClosing: no; FireExit: no; Infiltration: 0 m3/hour/m; HasDrive: yes; WaterTightnessRating: -; MechanicalLoadRating: -; WindLoadRating: -
Pset_DoorWindowGlazingType - Shading Coefficient: 0
Pset_ManufacturerTypeInformation - ModelReference: 0.000000; ProductionYear: 0
Name | In | OverallHeight (m) | OverallWidth (m) | Allright_Bauteil_ID
door | Architektur (TB 200-209) | 2.35 | 0.96 | 0200Mak0000040352
door | Architektur (TB 200-209) | 2.12 | 0.94 | 0200Mak0000036534
door | Architektur (TB 250-259) | 2.35 | 0.94 | 0250Mak0000009711

# IfcDoor: door (2)
Type - PredefinedType: DOOR; OperationType: SINGLE_SWING_RIGHT; ParameterTakesPrecedence: no
Type - IfcDoorLiningProperties - LiningDepth: 0.26 m; LiningThickness: 0.05 m
OverallWidth: 1.04 m
AllplanAttributes (door) - V6: 0 m; V7: 0 m; V8: 0 m; V9: 0; Programmversion: 3.0; Bezeichnung: door; Plugin_Bezeichnung: MainObject; Plugin_Objektname: SmartPartCompressed; Glasanteil_berücksichtigen: 100; Version: 7.0; Öffnungszweck: -; ProtectedOpening: no; Attributset-Objekt: Door; Abrechnungsart: St; Objektname: Türmakro, -SmartPart
AllplanQuantities - GlassSurface: 0; HeightWindowSillOutside: 0; HeightWindowSillInside: 0; OffsetOpeningBottom: 0; OffsetOpeningTop: 0; OffsetOpeningLeft: 0; OffsetOpeningRight: 0; DeductionOpeningBottom: 0; DeductionOpeningLeft: 50; DeductionOpeningRight: 50; DeductionOpeningTop: 50
Pset_DoorCommon - Status: NEW; IsExternal: yes; ThermalTransmittance: 0 W/K/m2; HandicapAccessible: no; SmokeStop: no; SelfClosing: no; FireExit: no; Infiltration: 0 m3/hour/m; HasDrive: yes; WaterTightnessRating: -; MechanicalLoadRating: -; WindLoadRating: -
Pset_DoorWindowGlazingType - Shading Coefficient: 0
Pset_ManufacturerTypeInformation - ModelReference: 0.000000; ProductionYear: 0
Name | In | OverallHeight (m) | Allright_Bauteil_ID
door | Architektur (TB 200-209) | 2.32 | 0200Mak0000036803
door | Architektur (TB 250-259) | 2.35 | 0250Mak0000009686

# IfcDoor: door
In: Architektur (TB 200-209)
Type - PredefinedType: DOOR; OperationType: SINGLE_SWING_RIGHT; ParameterTakesPrecedence: no
Type - IfcDoorLiningProperties - LiningDepth: 0.4 m; LiningThickness: 0.03 m
OverallHeight: 2.35 m; OverallWidth: 1.44 m
AllplanAttributes (door) - V6: 0 m; V7: 0 m; V8: 0 m; V9: 0; Programmversion: 3.0; Bezeichnung: door; Plugin_Bezeichnung: MainObject; Plugin_Objektname: SmartPartCompressed; Glasanteil_berücksichtigen: 100; Version: 7.0; Öffnungszweck: -; ProtectedOpening: no; Attributset-Objekt: Door; Allright_Bauteil_ID: 0200Mak0000031203; Abrechnungsart: St; Objektname: Türmakro, -SmartPart
AllplanQuantities - GlassSurface: 0; HeightWindowSillOutside: 0; HeightWindowSillInside: 0; OffsetOpeningBottom: 0; OffsetOpeningTop: 0; OffsetOpeningLeft: 0; OffsetOpeningRight: 0; DeductionOpeningBottom: 0; DeductionOpeningLeft: 30; DeductionOpeningRight: 30; DeductionOpeningTop: 30
Pset_DoorCommon - Status: NEW; IsExternal: yes; ThermalTransmittance: 0 W/K/m2; HandicapAccessible: no; SmokeStop: no; SelfClosing: no; FireExit: no; Infiltration: 0 m3/hour/m; HasDrive: yes; WaterTightnessRating: -; MechanicalLoadRating: -; WindLoadRating: -
Pset_DoorWindowGlazingType - Shading Coefficient: 0
Pset_ManufacturerTypeInformation - ModelReference: 0.000000; ProductionYear: 0

# IfcOpeningElement (64)
PredefinedType: OPENING
AllplanAttributes - Object Layer Attributes #1, Gewerk: Mauerarbeiten; Object Layer Attributes #1, Objektname: Türöffnung; Object Layer Attributes #1, Außenliegend: yes; Object Layer Attributes #1, Barrierefrei: no; Object Layer Attributes #1, Fluchtweg: no; Object Layer Attributes #1, Brandabschnittsdefinierendes Bauteil: no; Object Layer Attributes #1, Attributset-Objekt: OpeningElement; Object Layer Attributes #1, Abrechnungsart: m³
Pset_OpeningElementCommon - Status: NEW; FireExit: no; ProtectedOpening: yes
Name | In | Object Layer Attributes #1, Allright_Bauteil_ID
Window opening | Architektur (TB 200-209) | 0200Fen0000165101
Door opening | Architektur (TB 200-209) | 0200Tür0000043199 | AllplanAttributes - Object Layer Attributes #1, Türanschlag: -
Door opening | Architektur (TB 200-209) | 0200Tür0000043627 | AllplanAttributes - Object Layer Attributes #1, Türanschlag: -
Door opening | Architektur (TB 200-209) | 0200Tür0000036172 | AllplanAttributes - Object Layer Attributes #1, Türanschlag: DIN R
Door opening | Architektur (TB 200-209) | 0200Tür0000040341 | AllplanAttributes - Object Layer Attributes #1, Türanschlag: DIN L
Door opening | Architektur (TB 200-209) | 0200Tür0000040329 | AllplanAttributes - Object Layer Attributes #1, Türanschlag: DIN L; Object Layer Attributes #1, Versatz_oben: 0; Object Layer Attributes #1, Versatz_unten: 0
Door opening | Architektur (TB 200-209) | 0200Tür0000040317 | AllplanAttributes - Object Layer Attributes #1, Türanschlag: DIN L; Object Layer Attributes #1, Versatz_oben: 0; Object Layer Attributes #1, Versatz_unten: 0
Door opening | Architektur (TB 200-209) | 0200Tür0000040305 | AllplanAttributes - Object Layer Attributes #1, Türanschlag: DIN L; Object Layer Attributes #1, Versatz_oben: 0; Object Layer Attributes #1, Versatz_unten: 0
Door opening | Architektur (TB 200-209) | 0200Tür0000040089 | AllplanAttributes - Object Layer Attributes #1, Türanschlag: DIN L
Door opening | Architektur (TB 200-209) | 0200Tür0000041397 | AllplanAttributes - Object Layer Attributes #1, Türanschlag: -
Window opening | Architektur (TB 200-209) | 0200Fen0000040511
Window opening | Architektur (TB 200-209) | 0200Fen0000041846
Window opening | Architektur (TB 200-209) | 0200Fen0000041858
Window opening | Architektur (TB 200-209) | 0200Fen0000042176
Door opening | Architektur (TB 200-209) | 0200Tür0000042511 | AllplanAttributes - Object Layer Attributes #1, Türanschlag: -
Window opening | Architektur (TB 200-209) | 0200Fen0000039366
Window opening | Architektur (TB 200-209) | 0200Fen0000039300
Window opening | Architektur (TB 200-209) | 0200Fen0000038979
Window opening | Architektur (TB 200-209) | 0200Fen0000044411
Door opening | Architektur (TB 200-209) | 0200Tür0000035612 | AllplanAttributes - Object Layer Attributes #1, Türanschlag: -
Window opening | Architektur (TB 200-209) | 0200Fen0000137138
Window opening | Architektur (TB 200-209) | 0200Fen0000137110
Window opening | Architektur (TB 200-209) | 0200Fen0000137117
Window opening | Architektur (TB 200-209) | 0200Fen0000137124
Door opening | Architektur (TB 200-209) | 0200Tür0000031202 | AllplanAttributes - Object Layer Attributes #1, Türanschlag: DIN L
Door opening | Architektur (TB 200-209) | 0200Tür0000031206 | AllplanAttributes - Object Layer Attributes #1, Türanschlag: -
Door opening | Architektur (TB 200-209) | 0200Tür0000043901 | AllplanAttributes - Object Layer Attributes #1, Türanschlag: -
Door opening | Architektur (TB 200-209) | 0200Tür0000036792 | AllplanAttributes - Object Layer Attributes #1, Türanschlag: DIN L
Door opening | Architektur (TB 200-209) | 0200Tür0000037240 | AllplanAttributes - Object Layer Attributes #1, Türanschlag: -
Window opening | Architektur (TB 200-209) | 0200Fen0000053602
Door opening | Architektur (TB 200-209) | 0200Tür0000036523 | AllplanAttributes - Object Layer Attributes #1, Türanschlag: DIN L
Door opening | Architektur (TB 200-209) | 0200Tür0000036785 | AllplanAttributes - Object Layer Attributes #1, Türanschlag: -
Window opening | Architektur (TB 200-209) | 0200Fen0000137131
Door opening | Architektur (TB 200-209) | 0200Tür0000144879 | AllplanAttributes - Object Layer Attributes #1, Türanschlag: DIN R
Door opening | Architektur (TB 200-209) | 0200Tür0000144878 | AllplanAttributes - Object Layer Attributes #1, Türanschlag: -
Door opening | Architektur (TB 200-209) | 0200Tür0000137548 | AllplanAttributes - Object Layer Attributes #1, Türanschlag: -
Window opening | Architektur (TB 200-209) | 0200Fen0000038623
Window opening | Architektur (TB 200-209) | 0200Fen0000034633
Window opening | Architektur (TB 200-209) | 0200Fen0000156458
Window opening | Architektur (TB 200-209) | 0200Fen0000156852
Window opening | Architektur (TB 200-209) | 0200Fen0000002076 | AllplanAttributes - Object Layer Attributes #2, Versatz_oben: 0; Object Layer Attributes #2, Gewerk: Mauerarbeiten; Object Layer Attributes #2, Versatz_unten: 0; Object Layer Attributes #2, Allright_Bauteil_ID: 0200Fen0000165928; Object Layer Attributes #2, Abrechnungsart: m²; Object Layer Attributes #2, Objektname: Fensteröffnung; Object Layer Attributes #2, OpeningElementCommon, Status: Neubau; Object Layer Attributes #2, OpeningElementCommon, Notausgang: no; Object Layer Attributes #2, OpeningElementCommon, ProtectedOpening: yes; Object Layer Attributes #3, Versatz_oben: 0; Object Layer Attributes #3, Gewerk: Mauerarbeiten; Object Layer Attributes #3, Versatz_unten: 0; Object Layer Attributes #3, Allright_Bauteil_ID: 0200Fen0000165929; Object Layer Attributes #3, Abrechnungsart: m²; Object Layer Attributes #3, Objektname: Fensteröffnung; Object Layer Attributes #3, OpeningElementCommon, Status: Neubau; Object Layer Attributes #3, OpeningElementCommon, Notausgang: no; Object Layer Attributes #3, OpeningElementCommon, ProtectedOpening: yes
Window opening | Architektur (TB 200-209) | 0200Fen0000018075 | AllplanAttributes - Object Layer Attributes #2, Versatz_oben: 0; Object Layer Attributes #2, Gewerk: Mauerarbeiten; Object Layer Attributes #2, Versatz_unten: 0; Object Layer Attributes #2, Allright_Bauteil_ID: 0200Fen0000165976; Object Layer Attributes #2, Abrechnungsart: m²; Object Layer Attributes #2, Objektname: Fensteröffnung; Object Layer Attributes #2, OpeningElementCommon, Status: Neubau; Object Layer Attributes #2, OpeningElementCommon, Notausgang: no; Object Layer Attributes #2, OpeningElementCommon, ProtectedOpening: yes; Object Layer Attributes #3, Versatz_oben: 0; Object Layer Attributes #3, Gewerk: Mauerarbeiten; Object Layer Attributes #3, Versatz_unten: 0; Object Layer Attributes #3, Allright_Bauteil_ID: 0200Fen0000165977; Object Layer Attributes #3, Abrechnungsart: m²; Object Layer Attributes #3, Objektname: Fensteröffnung; Object Layer Attributes #3, OpeningElementCommon, Status: Neubau; Object Layer Attributes #3, OpeningElementCommon, Notausgang: no; Object Layer Attributes #3, OpeningElementCommon, ProtectedOpening: yes
Window opening | Architektur (TB 200-209) | 0200Fen0000018063 | AllplanAttributes - Object Layer Attributes #2, Versatz_oben: 0; Object Layer Attributes #2, Gewerk: Mauerarbeiten; Object Layer Attributes #2, Versatz_unten: 0; Object Layer Attributes #2, Allright_Bauteil_ID: 0200Fen0000165985; Object Layer Attributes #2, Abrechnungsart: m²; Object Layer Attributes #2, Objektname: Fensteröffnung; Object Layer Attributes #2, OpeningElementCommon, Status: Neubau; Object Layer Attributes #2, OpeningElementCommon, Notausgang: no; Object Layer Attributes #2, OpeningElementCommon, ProtectedOpening: yes; Object Layer Attributes #3, Versatz_oben: 0; Object Layer Attributes #3, Gewerk: Mauerarbeiten; Object Layer Attributes #3, Versatz_unten: 0; Object Layer Attributes #3, Allright_Bauteil_ID: 0200Fen0000165986; Object Layer Attributes #3, Abrechnungsart: m²; Object Layer Attributes #3, Objektname: Fensteröffnung; Object Layer Attributes #3, OpeningElementCommon, Status: Neubau; Object Layer Attributes #3, OpeningElementCommon, Notausgang: no; Object Layer Attributes #3, OpeningElementCommon, ProtectedOpening: yes
Window opening | Architektur (TB 200-209) | 0200Fen0000018051 | AllplanAttributes - Object Layer Attributes #2, Versatz_oben: 0; Object Layer Attributes #2, Gewerk: Mauerarbeiten; Object Layer Attributes #2, Versatz_unten: 0; Object Layer Attributes #2, Allright_Bauteil_ID: 0200Fen0000165994; Object Layer Attributes #2, Abrechnungsart: m²; Object Layer Attributes #2, Objektname: Fensteröffnung; Object Layer Attributes #2, OpeningElementCommon, Status: Neubau; Object Layer Attributes #2, OpeningElementCommon, Notausgang: no; Object Layer Attributes #2, OpeningElementCommon, ProtectedOpening: yes; Object Layer Attributes #3, Versatz_oben: 0; Object Layer Attributes #3, Gewerk: Mauerarbeiten; Object Layer Attributes #3, Versatz_unten: 0; Object Layer Attributes #3, Allright_Bauteil_ID: 0200Fen0000165995; Object Layer Attributes #3, Abrechnungsart: m²; Object Layer Attributes #3, Objektname: Fensteröffnung; Object Layer Attributes #3, OpeningElementCommon, Status: Neubau; Object Layer Attributes #3, OpeningElementCommon, Notausgang: no; Object Layer Attributes #3, OpeningElementCommon, ProtectedOpening: yes
Window opening | Architektur (TB 200-209) | 0200Fen0000018039 | AllplanAttributes - Object Layer Attributes #2, Versatz_oben: 0; Object Layer Attributes #2, Gewerk: Mauerarbeiten; Object Layer Attributes #2, Versatz_unten: 0; Object Layer Attributes #2, Allright_Bauteil_ID: 0200Fen0000166003; Object Layer Attributes #2, Abrechnungsart: m²; Object Layer Attributes #2, Objektname: Fensteröffnung; Object Layer Attributes #2, OpeningElementCommon, Status: Neubau; Object Layer Attributes #2, OpeningElementCommon, Notausgang: no; Object Layer Attributes #2, OpeningElementCommon, ProtectedOpening: yes; Object Layer Attributes #3, Versatz_oben: 0; Object Layer Attributes #3, Gewerk: Mauerarbeiten; Object Layer Attributes #3, Versatz_unten: 0; Object Layer Attributes #3, Allright_Bauteil_ID: 0200Fen0000166004; Object Layer Attributes #3, Abrechnungsart: m²; Object Layer Attributes #3, Objektname: Fensteröffnung; Object Layer Attributes #3, OpeningElementCommon, Status: Neubau; Object Layer Attributes #3, OpeningElementCommon, Notausgang: no; Object Layer Attributes #3, OpeningElementCommon, ProtectedOpening: yes
Door opening | Architektur (TB 250-259) | 0250Tür0000009695 | AllplanAttributes - Object Layer Attributes #1, Türanschlag: -
Door opening | Architektur (TB 250-259) | 0250Tür0000002730 | AllplanAttributes - Object Layer Attributes #1, Türanschlag: -
Door opening | Architektur (TB 250-259) | 0250Tür0000009682 | AllplanAttributes - Object Layer Attributes #1, Türanschlag: DIN L
Door opening | Architektur (TB 250-259) | 0250Tür0000009680 | AllplanAttributes - Object Layer Attributes #1, Türanschlag: -
Door opening | Architektur (TB 250-259) | 0250Tür0000009718 | AllplanAttributes - Object Layer Attributes #1, Türanschlag: -
Door opening | Architektur (TB 250-259) | 0250Tür0000009701 | AllplanAttributes - Object Layer Attributes #1, Türanschlag: DIN L
Door opening | Architektur (TB 250-259) | 0250Tür0000009703 | AllplanAttributes - Object Layer Attributes #1, Türanschlag: -
Window opening | Architektur (TB 250-259) | 0250Fen0000004705
Window opening | Architektur (TB 250-259) | 0250Fen0000005503
Window opening | Architektur (TB 250-259) | 0250Fen0000005544
Window opening | Architektur (TB 250-259) | 0250Fen0000024517
Window opening | Architektur (TB 250-259) | 0250Fen0000024519
Window opening | Architektur (TB 250-259) | 0250Fen0000024520
Window opening | Architektur (TB 250-259) | 0250Fen0000011175
Window opening | Architektur (TB 250-259) | 0250Fen0000031593
Window opening | Architektur (TB 250-259) | 0250Fen0000005877
Door opening | Architektur (TB 450-459) | 0450Tür0000016342 | AllplanAttributes - Object Layer Attributes #1, Türanschlag: DIN R
Door opening | Architektur (TB 450-459) | 0450Tür0000062059 | AllplanAttributes - Object Layer Attributes #1, Türanschlag: DIN R
Door opening | Architektur (TB 450-459) | 0450Tür0000062489 | AllplanAttributes - Object Layer Attributes #1, Türanschlag: DIN L

# IfcOpeningElement: Opening (28)
Pset_OpeningElementCommon - Status: NEW
Name | In | Object Layer Attributes #1, Versatz_oben = Object Layer Attributes #1, Versatz_unten | Object Layer Attributes #1, Gewerk | Object Layer Attributes #1, Allright_Bauteil_ID | Object Layer Attributes #1, Abrechnungsart | Object Layer Attributes #1, Objektname
Wall Niche | Architektur (TB 200-209) | 0 | Mauerarbeiten | 0200Wni0000165052 | m³ | Wandnische
Wall Niche | Architektur (TB 200-209) | 0 | Betonarbeiten | 0200Wni0000039565 | m³ | Wandnische
Wall Niche | Architektur (TB 200-209) | 0 | Betonarbeiten | 0200Wni0000039557 | m³ | Wandnische
Wall Niche | Architektur (TB 200-209) | 0 | Betonarbeiten | 0200Wni0000039541 | m³ | Wandnische
Wall Niche | Architektur (TB 200-209) | 0 | Betonarbeiten | 0200Wni0000108883 | m³ | Wandnische
Wall Niche | Architektur (TB 200-209) | 0 | Betonarbeiten | 0200Wni0000165447 | m³ | Wandnische
Wall Niche | Architektur (TB 200-209) | 0 | Mauerarbeiten | 0200Wni0000048349 | m³ | Wandnische
Wall Niche | Architektur (TB 200-209) | 0 | Betonarbeiten | 0200Wni0000138262 | m³ | Wandnische
Wall Niche | Architektur (TB 200-209) | 0 | Betonarbeiten | 0200Wni0000034227 | m³ | Wandnische
Wall Niche | Architektur (TB 200-209) | 0 |  | 0200Wni0000138506 | m² | Wandnische | AllplanAttributes - Object Layer Attributes #2, Status: Neubau; Object Layer Attributes #2, Versatz_oben: 0; Object Layer Attributes #2, Versatz_unten: 0; Object Layer Attributes #2, Allright_Bauteil_ID: 0200Wni0000165925; Object Layer Attributes #2, Abrechnungsart: m²; Object Layer Attributes #2, Objektname: Wandnische
Wall Niche | Architektur (TB 200-209) | 0 |  | 0200Wni0000052376 | m² | Wandnische | AllplanAttributes - Object Layer Attributes #2, Status: Neubau; Object Layer Attributes #2, Versatz_oben: 0; Object Layer Attributes #2, Versatz_unten: 0; Object Layer Attributes #2, Allright_Bauteil_ID: 0200Wni0000166012; Object Layer Attributes #2, Abrechnungsart: m²; Object Layer Attributes #2, Objektname: Wandnische
Wall Niche | Architektur (TB 200-209) | 0 |  | 0200Wni0000052354 | m² | Wandnische | AllplanAttributes - Object Layer Attributes #2, Status: Neubau; Object Layer Attributes #2, Versatz_oben: 0; Object Layer Attributes #2, Versatz_unten: 0; Object Layer Attributes #2, Allright_Bauteil_ID: 0200Wni0000166015; Object Layer Attributes #2, Abrechnungsart: m²; Object Layer Attributes #2, Objektname: Wandnische
Wall Niche | Architektur (TB 200-209) | 0 |  | 0200Wni0000052332 | m² | Wandnische | AllplanAttributes - Object Layer Attributes #2, Status: Neubau; Object Layer Attributes #2, Versatz_oben: 0; Object Layer Attributes #2, Versatz_unten: 0; Object Layer Attributes #2, Allright_Bauteil_ID: 0200Wni0000166018; Object Layer Attributes #2, Abrechnungsart: m²; Object Layer Attributes #2, Objektname: Wandnische
Wall Niche | Architektur (TB 200-209) | 0 |  | 0200Wni0000052310 | m² | Wandnische | AllplanAttributes - Object Layer Attributes #2, Status: Neubau; Object Layer Attributes #2, Versatz_oben: 0; Object Layer Attributes #2, Versatz_unten: 0; Object Layer Attributes #2, Allright_Bauteil_ID: 0200Wni0000166021; Object Layer Attributes #2, Abrechnungsart: m²; Object Layer Attributes #2, Objektname: Wandnische
Wall Niche | Architektur (TB 200-209) | 0 |  | 0200Wni0000017751 | m² | Wandnische | AllplanAttributes - Object Layer Attributes #2, Status: Neubau; Object Layer Attributes #2, Versatz_oben: 0; Object Layer Attributes #2, Versatz_unten: 0; Object Layer Attributes #2, Allright_Bauteil_ID: 0200Wni0000166024; Object Layer Attributes #2, Abrechnungsart: m²; Object Layer Attributes #2, Objektname: Wandnische
Wall Niche | Architektur (TB 250-259) | 0 | Betonarbeiten | 0250Wni0000002673 | m³ | Wandnische
Wall Niche | Architektur (TB 250-259) | 0 | Betonarbeiten | 0250Wni0000002677 | m³ | Wandnische
Wall Niche | Architektur (TB 250-259) | 0 | Betonarbeiten | 0250Wni0000016639 | m³ | Wandnische
Wall Niche | Architektur (TB 250-259) | 0 | Betonarbeiten | 0250Wni0000024515 | m³ | Wandnische
Wall Niche | Architektur (TB 250-259) | 0 | Betonarbeiten | 0250Wni0000024516 | m³ | Wandnische
Wall Niche | Architektur (TB 250-259) | 0 | Betonarbeiten | 0250Wni0000024518 | m³ | Wandnische
Wall Niche | Architektur (TB 250-259) | 0 | Betonarbeiten | 0250Wni0000031610 | m³ | Wandnische
Wall Niche | Architektur (TB 250-259) | 0 | Betonarbeiten | 0250Wni0000026903 | m³ | Wandnische
Skylight | Architektur (TB 250-259) |  |  | 0252Dhö0000000035 | m² | Dachflächenfenster | AllplanAttributes - Object Layer Attributes #1, Material: Skylight
Skylight | Architektur (TB 450-459) |  |  | 0452Dhö0000000013 | m² | Dachflächenfenster | AllplanAttributes - Object Layer Attributes #1, Material: Skylight
Skylight | Architektur (TB 450-459) |  |  | 0452Dhö0000000027 | m² | Dachflächenfenster | AllplanAttributes - Object Layer Attributes #1, Material: Skylight
Skylight | Architektur (TB 450-459) |  |  | 0452Dhö0000000022 | m² | Dachflächenfenster | AllplanAttributes - Object Layer Attributes #1, Material: Skylight
Skylight | Architektur (TB 450-459) |  |  | 0452Dhö0000000017 | m² | Dachflächenfenster | AllplanAttributes - Object Layer Attributes #1, Material: Skylight

# IfcOpeningElement: Recess, Slab Recess
In: Architektur (TB 200-209)
AllplanAttributes - Object Layer Attributes #1, Allright_Bauteil_ID: 0201Das0000000478; Object Layer Attributes #1, Abrechnungsart: m²; Object Layer Attributes #1, Objektname: Deckenaussparung
Pset_OpeningElementCommon - Status: NEW; FireExit: no; ProtectedOpening: yes

# IfcRailing (4)
Material: steel
AllplanAttributes - Gewerk: Metallbau-, Schlosserarbeiten; V6: 0 m; V7: 0 m; V8: 0 m; V9: 0; Bauteil: Rail_Object; Material: steel; Plugin_Bezeichnung: Rail_Path; Plugin_Objektname: Rail_Macro; Höhe (h): 0 m; Durchmesser (d): 0 m; Attributset-Objekt: Railing; Abrechnungsart: St
Pset_RailingCommon - Status: NEW
Name | In | PredefinedType | Länge (m) | Objektname | Bezeichnung | Allright_Bauteil_ID | IsExternal
handrail with wall bracket | Architektur (TB 200-209) | HANDRAIL | 8.995 | Handlauf | handrail with wall bracket | 0206Gel0000000044 | no
railing simpel | Architektur (TB 200-209) | USERDEFINED | 4.785 | Geländer | railing simpel | 0206Gel0000000058 | yes
handrail with wall bracket | Architektur (TB 250-259) | HANDRAIL | 8.75 | Handlauf | handrail with wall bracket | 0256Gel0000000068 | no
railing simpel | Architektur (TB 250-259) | USERDEFINED | 4.958 | Geländer | railing simpel | 0256Gel0000000114 | yes

# IfcRoof (5)
AllplanAttributes - Object Layer Attributes #1, Brennbares Material: no; Object Layer Attributes #1, Brandabschnittsdefinierendes Bauteil: no; Object Layer Attributes #1, Raumhohe Wand: yes; Object Layer Attributes #1, Abrechnungsart: m²; Object Layer Attributes #1, Objektname: Dachhautschicht
Pset_RoofCommon - Status: NEW; IsExternal: no; ThermalTransmittance: 0 W/K/m2
Name | In | Object Layer Attributes #1, Allright_Bauteil_ID
 | Architektur (TB 200-209) | 0202Dah0000000008
 | Architektur (TB 250-259) | 0252Dah0000000030
 | Architektur (TB 250-259) | 0252Dah0000000070
 | Architektur (TB 250-259) | 0253Dah0000006193
 | Architektur (TB 450-459) | 0452Dah0000000010

# IfcSlab (18)
Name | In | PredefinedType | 2D Interaktion | Allright_Bauteil_ID | Abrechnungsart | Objektname | Status | IsExternal = Combustible = Compartmentation | ThermalTransmittance (W/K/m2) = PitchAngle (deg) | Volumen
 | Architektur (TB 200-209) | FLOOR | yes | 0201De 0000001082 | m² | Decke | NEW | no | 0 | 0.10872
 | Architektur (TB 200-209) | FLOOR | yes | 0201De 0000001080 | m² | Decke | NEW | no | 0 | 1.0506
 | Architektur (TB 200-209) | FLOOR | yes | 0201De 0000001575 | m² | Decke | NEW | no | 0 | 2.54001
 | Architektur (TB 200-209) | FLOOR | yes | 0201De 0000000033 | m² | Decke | NEW | no | 0 | 133.849
 | Architektur (TB 250-259) | FLOOR | yes | 0250De 0000010985 | m² | Decke | NEW | no | 0 | 0.11771
 | Architektur (TB 250-259) | FLOOR | yes | 0250De 0000028217 | m² | Decke | NEW | no | 0 | 0.0556163
 | Architektur (TB 250-259) | FLOOR | yes | 0251De 0000000004 | m² | Decke | NEW | no | 0 | 5.55651
 | Architektur (TB 250-259) | FLOOR | yes | 0251De 0000001701 | m² | Decke | NEW | no | 0 | 6.76362
 | Architektur (TB 250-259) | FLOOR | yes | 0251De 0000000009 | m² | Decke | NEW | no | 0 | 19.4583
 | Architektur (TB 250-259) | FLOOR | yes | 0251De 0000001679 | m² | Decke | NEW | no | 0 | 0.23345
 | Architektur (TB 250-259) | FLOOR | yes | 0251De 0000001370 | m² | Decke | NEW | no | 0 | 48.7304
2 x  | Architektur (TB 250-259) | ROOF
 | Architektur (TB 450-459) | FLOOR | yes | 0450De 0000016787 | m² | Decke | NEW | no | 0 | 0.10823
 | Architektur (TB 450-459) | FLOOR | yes | 0451De 0000000065 | m² | Decke | NEW | no | 0 | 19.21
 | Architektur (TB 450-459) | FLOOR | yes | 0451De 0000000052 | m² | Decke | NEW | no | 0 | 6.00768
2 x  | Architektur (TB 450-459) | ROOF

# IfcStair (3)
Material: Free-Form Stair
AllplanAttributes - Material: Free-Form Stair; Abrechnungsart: St; Objektname: Treppe
Pset_StairCommon - IsExternal: no; ThermalTransmittance: 0 W/K/m2; HandicapAccessible: no; FireExit: no; HasNonSkidSurface: no; NosingLength: 0 m
Name | In | Allright_Bauteil_ID | NumberOfRiser = NumberOfTreads | RiserHeight (m) | TreadLength (m)
 | Architektur (TB 200-209) | 0206Tre0000000042 | 19 | 1.905 | 2.66
 | Architektur (TB 250-259) | 0256Tre0000000040 | 18 | 2.133 | 2.832
 | Architektur (TB 250-259) | 0256Tre0000000202 | 6 | 2.017 | 1.867

# IfcWall (161)
PredefinedType: USERDEFINED
AllplanAttributes - Abrechnungsart: St; Objektname: Gesamtwand; Object Layer Attributes #1, 2D Interaktion: yes; Object Layer Attributes #1, Abrechnungsart: m³; Object Layer Attributes #1, Objektname: Wand; Object Layer Attributes #1, WallCommon, Status: Neubau; Object Layer Attributes #1, WallCommon, Brennbares Material: no; Object Layer Attributes #1, WallCommon, Brandabschnittsdefinierendes Bauteil: no; Object Layer Attributes #1, WallCommon, Raumhohe Wand: yes
Pset_WallCommon - Status: NEW; LoadBearing: yes; ThermalTransmittance: 0 W/K/m2; Combustible: no; Compartmentation: no; ExtendToStructure: yes
Name | In | Material | Bezeichnung | Allright_Bauteil_ID | Object Layer Attributes #1, Gewerk | Object Layer Attributes #1, Material | Object Layer Attributes #1, Betonfestigkeitsklasse | Object Layer Attributes #1, Allright_Bauteil_ID | IsExternal
reinforced - bearing | Architektur (TB 200-209) | concrete 0.25 m | reinforced - bearing | 0200HWa0000000891 | Betonarbeiten | concrete | C | 0200Wa 0000000892 | yes
reinforced - bearing | Architektur (TB 200-209) | concrete 0.08 m | reinforced - bearing | 0200HWa0000001110 | Betonarbeiten | concrete | C | 0200Wa 0000001111 | yes
reinforced - bearing | Architektur (TB 200-209) | concrete 0.08 m | reinforced - bearing | 0200HWa0000001132 | Betonarbeiten | concrete | C | 0200Wa 0000001133 | yes
masonry load-bearing | Architektur (TB 200-209) | masonry 0.13 m | masonry load-bearing | 0200HWa0000001443 | Mauerarbeiten | masonry |  | 0200Wa 0000001444 | no | AllplanAttributes - Object Layer Attributes #1, Bezeichnung: masonry; Object Layer Attributes #1, Material Architektur: ma; Object Layer Attributes #1, WallCommon, Tragendes Bauteil: yes
masonry load-bearing | Architektur (TB 200-209) | masonry 0.26 m | masonry load-bearing | 0200HWa0000001491 | Mauerarbeiten | masonry |  | 0200Wa 0000001492 | no | AllplanAttributes - Object Layer Attributes #1, Bezeichnung: masonry; Object Layer Attributes #1, Material Architektur: ma; Object Layer Attributes #1, WallCommon, Tragendes Bauteil: yes
masonry load-bearing | Architektur (TB 200-209) | masonry 0.13 m | masonry load-bearing | 0200HWa0000001545 | Mauerarbeiten | masonry |  | 0200Wa 0000001546 | no | AllplanAttributes - Object Layer Attributes #1, WallCommon, Außenliegend: no; Object Layer Attributes #1, WallCommon, U-Wert: 0
masonry load-bearing | Architektur (TB 200-209) | masonry 0.05 m | masonry load-bearing | 0200HWa0000001570 | Mauerarbeiten | masonry |  | 0200Wa 0000001571 | no | AllplanAttributes - Object Layer Attributes #1, WallCommon, Außenliegend: no; Object Layer Attributes #1, WallCommon, U-Wert: 0
masonry load-bearing | Architektur (TB 200-209) | masonry 0.08 m | masonry load-bearing | 0200HWa0000001560 | Mauerarbeiten | masonry |  | 0200Wa 0000001561 | no | AllplanAttributes - Object Layer Attributes #1, WallCommon, Außenliegend: no; Object Layer Attributes #1, WallCommon, U-Wert: 0
masonry load-bearing | Architektur (TB 200-209) | masonry 0.05 m | masonry load-bearing | 0200HWa0000001669 | Mauerarbeiten | masonry |  | 0200Wa 0000001670 | no | AllplanAttributes - Object Layer Attributes #1, WallCommon, Außenliegend: no; Object Layer Attributes #1, WallCommon, U-Wert: 0
masonry load-bearing | Architektur (TB 200-209) | masonry 0.05 m | masonry load-bearing | 0200HWa0000001684 | Mauerarbeiten | masonry |  | 0200Wa 0000001685 | no | AllplanAttributes - Object Layer Attributes #1, WallCommon, Außenliegend: no; Object Layer Attributes #1, WallCommon, U-Wert: 0
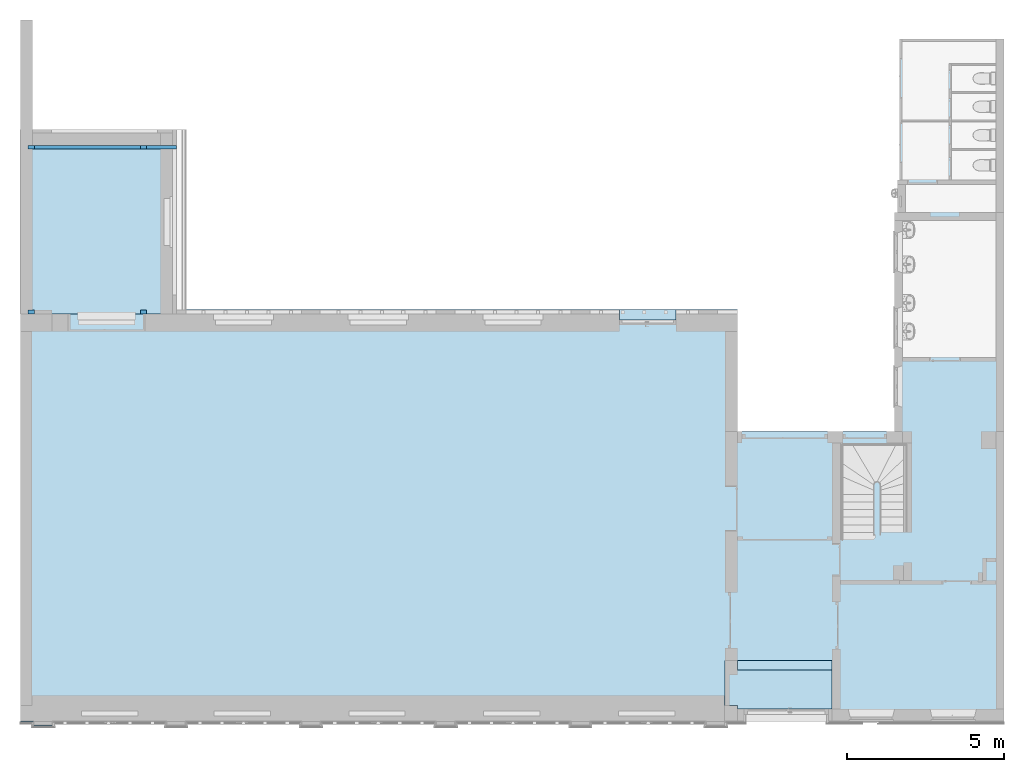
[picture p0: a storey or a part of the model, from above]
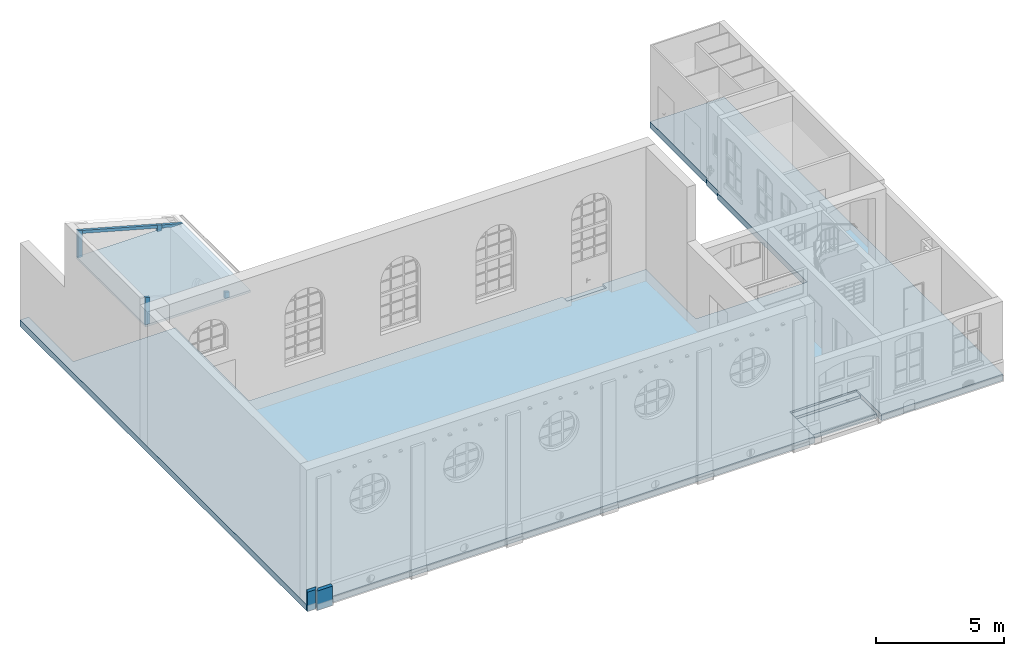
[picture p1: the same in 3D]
Properties of the parts of a building model (IFC4), part 2 of 2

# IfcWall (161)
Name | In | Material | Bezeichnung | Allright_Bauteil_ID | Object Layer Attributes #1, Gewerk | Object Layer Attributes #1, Material | Object Layer Attributes #1, Betonfestigkeitsklasse | Object Layer Attributes #1, Allright_Bauteil_ID | IsExternal
masonry load-bearing | Architektur (TB 200-209) | masonry 0.05 m | masonry load-bearing | 0200HWa0000001699 | Mauerarbeiten | masonry |  | 0200Wa 0000001700 | no | AllplanAttributes - Object Layer Attributes #1, WallCommon, Außenliegend: no; Object Layer Attributes #1, WallCommon, U-Wert: 0
masonry load-bearing | Architektur (TB 200-209) | masonry 0.05 m | masonry load-bearing | 0200HWa0000001714 | Mauerarbeiten | masonry |  | 0200Wa 0000001715 | no | AllplanAttributes - Object Layer Attributes #1, WallCommon, Außenliegend: no; Object Layer Attributes #1, WallCommon, U-Wert: 0
reinforced - bearing | Architektur (TB 200-209) | concrete 0.36 m | reinforced - bearing | 0200HWa0000000021 | Betonarbeiten | concrete | C | 0200Wa 0000000022 | yes | AllplanAttributes - Object Layer Attributes #1, Bezeichnung: concrete reinforced load-bearing; Object Layer Attributes #1, WallCommon, Tragendes Bauteil: yes
reinforced - bearing | Architektur (TB 200-209) | concrete 0.56 m | reinforced - bearing | 0200HWa0000000242 | Betonarbeiten | concrete | C | 0200Wa 0000000243 | yes | AllplanAttributes - Object Layer Attributes #1, WallCommon, Tragendes Bauteil: no
reinforced - bearing | Architektur (TB 200-209) | concrete 0.25 m | reinforced - bearing | 0200HWa0000000316 | Betonarbeiten | concrete | C | 0200Wa 0000000317 | yes
reinforced - bearing | Architektur (TB 200-209) | concrete 0.4 m | reinforced - bearing | 0200HWa0000048626 | Betonarbeiten | concrete | C | 0200Wa 0000048637 | yes | AllplanAttributes - Object Layer Attributes #1, WallCommon, Tragendes Bauteil: no
reinforced - bearing | Architektur (TB 200-209) | concrete 0.56 m | reinforced - bearing | 0200HWa0000000247 | Betonarbeiten | concrete | C | 0200Wa 0000000248 | yes | AllplanAttributes - Object Layer Attributes #1, WallCommon, Tragendes Bauteil: no
reinforced - bearing | Architektur (TB 200-209) | concrete 0.12 m | reinforced - bearing | 0200HWa0000059159 | Betonarbeiten | concrete | C | 0200Wa 0000059161 | yes | AllplanAttributes - Object Layer Attributes #1, WallCommon, Außenliegend: no; Object Layer Attributes #1, WallCommon, U-Wert: 0
reinforced - bearing | Architektur (TB 200-209) | concrete 0.39 m | reinforced - bearing | 0200HWa0000000213 | Betonarbeiten | concrete | C | 0200Wa 0000000215 | yes | AllplanAttributes - Object Layer Attributes #1, Bezeichnung: concrete reinforced load-bearing; Object Layer Attributes #1, WallCommon, Tragendes Bauteil: yes
reinforced - bearing | Architektur (TB 200-209) | concrete 0.39 m | reinforced - bearing | 0200HWa0000000388 | Betonarbeiten | concrete | C | 0200Wa 0000000389 | yes | AllplanAttributes - Object Layer Attributes #1, Bezeichnung: concrete reinforced load-bearing; Object Layer Attributes #1, WallCommon, Tragendes Bauteil: yes
reinforced - bearing | Architektur (TB 200-209) | concrete 0.39 m | reinforced - bearing | 0200HWa0000000378 | Betonarbeiten | concrete | C | 0200Wa 0000000379 | yes | AllplanAttributes - Object Layer Attributes #1, Bezeichnung: concrete reinforced load-bearing; Object Layer Attributes #1, WallCommon, Tragendes Bauteil: yes
reinforced - bearing | Architektur (TB 200-209) | concrete 0.12 m | reinforced - bearing | 0200HWa0000051963 | Betonarbeiten | concrete | C | 0200Wa 0000051964 | yes
reinforced - bearing | Architektur (TB 200-209) | concrete 0.12 m | reinforced - bearing | 0200HWa0000051952 | Betonarbeiten | concrete | C | 0200Wa 0000051953 | yes
reinforced - bearing | Architektur (TB 200-209) | concrete 0.12 m | reinforced - bearing | 0200HWa0000000439 | Betonarbeiten | concrete | C | 0200Wa 0000000440 | yes
reinforced - bearing | Architektur (TB 200-209) | concrete 0.12 m | reinforced - bearing | 0200HWa0000000449 | Betonarbeiten | concrete | C | 0200Wa 0000000450 | yes
masonry load-bearing | Architektur (TB 200-209) | masonry 0.57 m | masonry load-bearing | 0200HWa0000001332 | Mauerarbeiten | masonry |  | 0200Wa 0000001333 | no | AllplanAttributes - Object Layer Attributes #1, Bezeichnung: masonry; Object Layer Attributes #1, Material Architektur: ma; Object Layer Attributes #1, WallCommon, Tragendes Bauteil: yes
reinforced - bearing | Architektur (TB 200-209) | concrete 0.51 m | reinforced - bearing | 0200HWa0000049038 | Betonarbeiten | concrete | C | 0200Wa 0000049040 | yes | AllplanAttributes - Object Layer Attributes #1, Bezeichnung: concrete reinforced load-bearing; Object Layer Attributes #1, WallCommon, Tragendes Bauteil: yes
reinforced - bearing | Architektur (TB 200-209) | concrete 0.02 m | reinforced - bearing | 0200HWa0000134526 | Betonarbeiten | concrete | C | 0200Wa 0000134527 | yes | AllplanAttributes - Object Layer Attributes #1, WallCommon, Außenliegend: no; Object Layer Attributes #1, WallCommon, U-Wert: 0
reinforced - bearing | Architektur (TB 200-209) | concrete 0.02 m | reinforced - bearing | 0200HWa0000134536 | Betonarbeiten | concrete | C | 0200Wa 0000134537 | yes | AllplanAttributes - Object Layer Attributes #1, WallCommon, Außenliegend: no; Object Layer Attributes #1, WallCommon, U-Wert: 0
reinforced - bearing | Architektur (TB 200-209) | concrete 0.02 m | reinforced - bearing | 0200HWa0000134551 | Betonarbeiten | concrete | C | 0200Wa 0000134552 | yes | AllplanAttributes - Object Layer Attributes #1, WallCommon, Außenliegend: no; Object Layer Attributes #1, WallCommon, U-Wert: 0
reinforced - bearing | Architektur (TB 200-209) | concrete 0.02 m | reinforced - bearing | 0200HWa0000134570 | Betonarbeiten | concrete | C | 0200Wa 0000134571 | yes | AllplanAttributes - Object Layer Attributes #1, WallCommon, Außenliegend: no; Object Layer Attributes #1, WallCommon, U-Wert: 0
reinforced - bearing | Architektur (TB 200-209) | concrete 0.02 m | reinforced - bearing | 0200HWa0000134591 | Betonarbeiten | concrete | C | 0200Wa 0000134592 | yes | AllplanAttributes - Object Layer Attributes #1, WallCommon, Außenliegend: no; Object Layer Attributes #1, WallCommon, U-Wert: 0
reinforced - bearing | Architektur (TB 200-209) | concrete 0.02 m | reinforced - bearing | 0200HWa0000134607 | Betonarbeiten | concrete | C | 0200Wa 0000134608 | yes | AllplanAttributes - Object Layer Attributes #1, WallCommon, Außenliegend: no; Object Layer Attributes #1, WallCommon, U-Wert: 0
reinforced - bearing | Architektur (TB 200-209) | concrete 0.02 m | reinforced - bearing | 0200HWa0000134625 | Betonarbeiten | concrete | C | 0200Wa 0000134626 | yes | AllplanAttributes - Object Layer Attributes #1, WallCommon, Außenliegend: no; Object Layer Attributes #1, WallCommon, U-Wert: 0
reinforced - bearing | Architektur (TB 200-209) | concrete 0.02 m | reinforced - bearing | 0200HWa0000134644 | Betonarbeiten | concrete | C | 0200Wa 0000134645 | yes | AllplanAttributes - Object Layer Attributes #1, WallCommon, Außenliegend: no; Object Layer Attributes #1, WallCommon, U-Wert: 0
reinforced - bearing | Architektur (TB 200-209) | concrete 0.02 m | reinforced - bearing | 0200HWa0000134706 | Betonarbeiten | concrete | C | 0200Wa 0000134707 | yes | AllplanAttributes - Object Layer Attributes #1, WallCommon, Außenliegend: no; Object Layer Attributes #1, WallCommon, U-Wert: 0
reinforced - bearing | Architektur (TB 200-209) | concrete 0.02 m | reinforced - bearing | 0200HWa0000134719 | Betonarbeiten | concrete | C | 0200Wa 0000134720 | yes | AllplanAttributes - Object Layer Attributes #1, WallCommon, Außenliegend: no; Object Layer Attributes #1, WallCommon, U-Wert: 0
reinforced - bearing | Architektur (TB 200-209) | concrete 0.02 m | reinforced - bearing | 0200HWa0000134734 | Betonarbeiten | concrete | C | 0200Wa 0000134735 | yes | AllplanAttributes - Object Layer Attributes #1, WallCommon, Außenliegend: no; Object Layer Attributes #1, WallCommon, U-Wert: 0
reinforced - bearing | Architektur (TB 200-209) | concrete 0.02 m | reinforced - bearing | 0200HWa0000134751 | Betonarbeiten | concrete | C | 0200Wa 0000134752 | yes | AllplanAttributes - Object Layer Attributes #1, WallCommon, Außenliegend: no; Object Layer Attributes #1, WallCommon, U-Wert: 0
reinforced - bearing | Architektur (TB 200-209) | concrete 0.02 m | reinforced - bearing | 0200HWa0000134772 | Betonarbeiten | concrete | C | 0200Wa 0000134773 | yes | AllplanAttributes - Object Layer Attributes #1, WallCommon, Außenliegend: no; Object Layer Attributes #1, WallCommon, U-Wert: 0
reinforced - bearing | Architektur (TB 200-209) | concrete 0.02 m | reinforced - bearing | 0200HWa0000134788 | Betonarbeiten | concrete | C | 0200Wa 0000134789 | yes | AllplanAttributes - Object Layer Attributes #1, WallCommon, Außenliegend: no; Object Layer Attributes #1, WallCommon, U-Wert: 0
reinforced - bearing | Architektur (TB 200-209) | concrete 0.02 m | reinforced - bearing | 0200HWa0000134808 | Betonarbeiten | concrete | C | 0200Wa 0000134809 | yes | AllplanAttributes - Object Layer Attributes #1, WallCommon, Außenliegend: no; Object Layer Attributes #1, WallCommon, U-Wert: 0
reinforced - bearing | Architektur (TB 200-209) | concrete 0.02 m | reinforced - bearing | 0200HWa0000134827 | Betonarbeiten | concrete | C | 0200Wa 0000134828 | yes | AllplanAttributes - Object Layer Attributes #1, WallCommon, Außenliegend: no; Object Layer Attributes #1, WallCommon, U-Wert: 0
reinforced - bearing | Architektur (TB 200-209) | concrete 0.02 m | reinforced - bearing | 0200HWa0000134848 | Betonarbeiten | concrete | C | 0200Wa 0000134849 | yes | AllplanAttributes - Object Layer Attributes #1, WallCommon, Außenliegend: no; Object Layer Attributes #1, WallCommon, U-Wert: 0
reinforced - bearing | Architektur (TB 200-209) | concrete 0.02 m | reinforced - bearing | 0200HWa0000134864 | Betonarbeiten | concrete | C | 0200Wa 0000134865 | yes | AllplanAttributes - Object Layer Attributes #1, WallCommon, Außenliegend: no; Object Layer Attributes #1, WallCommon, U-Wert: 0
reinforced - bearing | Architektur (TB 200-209) | concrete 0.02 m | reinforced - bearing | 0200HWa0000134882 | Betonarbeiten | concrete | C | 0200Wa 0000134883 | yes | AllplanAttributes - Object Layer Attributes #1, WallCommon, Außenliegend: no; Object Layer Attributes #1, WallCommon, U-Wert: 0
reinforced - bearing | Architektur (TB 200-209) | concrete 0.02 m | reinforced - bearing | 0200HWa0000134903 | Betonarbeiten | concrete | C | 0200Wa 0000134904 | yes | AllplanAttributes - Object Layer Attributes #1, WallCommon, Außenliegend: no; Object Layer Attributes #1, WallCommon, U-Wert: 0
reinforced - bearing | Architektur (TB 200-209) | concrete 0.05 m | reinforced - bearing | 0200HWa0000056707 | Betonarbeiten | concrete | C | 0200Wa 0000056709 | yes | AllplanAttributes - Object Layer Attributes #1, WallCommon, Außenliegend: no; Object Layer Attributes #1, WallCommon, U-Wert: 0
reinforced - bearing | Architektur (TB 200-209) | concrete 0.05 m | reinforced - bearing | 0200HWa0000135835 | Betonarbeiten | concrete | C | 0200Wa 0000135837 | yes | AllplanAttributes - Object Layer Attributes #1, WallCommon, Außenliegend: no; Object Layer Attributes #1, WallCommon, U-Wert: 0
reinforced - bearing | Architektur (TB 200-209) | concrete 0.05 m | reinforced - bearing | 0200HWa0000136051 | Betonarbeiten | concrete | C | 0200Wa 0000136053 | yes | AllplanAttributes - Object Layer Attributes #1, WallCommon, Außenliegend: no; Object Layer Attributes #1, WallCommon, U-Wert: 0
reinforced - bearing | Architektur (TB 200-209) | concrete 0.05 m | reinforced - bearing | 0200HWa0000136169 | Betonarbeiten | concrete | C | 0200Wa 0000136171 | yes | AllplanAttributes - Object Layer Attributes #1, WallCommon, Außenliegend: no; Object Layer Attributes #1, WallCommon, U-Wert: 0
reinforced - bearing | Architektur (TB 200-209) | concrete 0.05 m | reinforced - bearing | 0200HWa0000136456 | Betonarbeiten | concrete | C | 0200Wa 0000136458 | yes | AllplanAttributes - Object Layer Attributes #1, WallCommon, Außenliegend: no; Object Layer Attributes #1, WallCommon, U-Wert: 0
reinforced - bearing | Architektur (TB 200-209) | concrete 0.05 m | reinforced - bearing | 0200HWa0000136545 | Betonarbeiten | concrete | C | 0200Wa 0000136551 | yes | AllplanAttributes - Object Layer Attributes #1, WallCommon, Außenliegend: no; Object Layer Attributes #1, WallCommon, U-Wert: 0
reinforced - bearing | Architektur (TB 200-209) | concrete 0.05 m | reinforced - bearing | 0200HWa0000136548 | Betonarbeiten | concrete | C | 0200Wa 0000136554 | yes | AllplanAttributes - Object Layer Attributes #1, WallCommon, Außenliegend: no; Object Layer Attributes #1, WallCommon, U-Wert: 0
reinforced - bearing | Architektur (TB 200-209) | concrete 0.05 m | reinforced - bearing | 0200HWa0000136544 | Betonarbeiten | concrete | C | 0200Wa 0000136555 | yes | AllplanAttributes - Object Layer Attributes #1, WallCommon, Außenliegend: no; Object Layer Attributes #1, WallCommon, U-Wert: 0
reinforced - bearing | Architektur (TB 200-209) | concrete 0.05 m | reinforced - bearing | 0200HWa0000136747 | Betonarbeiten | concrete | C | 0200Wa 0000136758 | yes | AllplanAttributes - Object Layer Attributes #1, WallCommon, Außenliegend: no; Object Layer Attributes #1, WallCommon, U-Wert: 0
reinforced - bearing | Architektur (TB 200-209) | concrete 0.05 m | reinforced - bearing | 0200HWa0000136749 | Betonarbeiten | concrete | C | 0200Wa 0000136759 | yes | AllplanAttributes - Object Layer Attributes #1, WallCommon, Außenliegend: no; Object Layer Attributes #1, WallCommon, U-Wert: 0
reinforced - bearing | Architektur (TB 200-209) | concrete 0.05 m | reinforced - bearing | 0200HWa0000136754 | Betonarbeiten | concrete | C | 0200Wa 0000136757 | yes | AllplanAttributes - Object Layer Attributes #1, WallCommon, Außenliegend: no; Object Layer Attributes #1, WallCommon, U-Wert: 0
reinforced - bearing | Architektur (TB 200-209) | concrete 0.05 m | reinforced - bearing | 0200HWa0000136785 | Betonarbeiten | concrete | C | 0200Wa 0000136795 | yes | AllplanAttributes - Object Layer Attributes #1, WallCommon, Außenliegend: no; Object Layer Attributes #1, WallCommon, U-Wert: 0
reinforced - bearing | Architektur (TB 200-209) | concrete 0.05 m | reinforced - bearing | 0200HWa0000136787 | Betonarbeiten | concrete | C | 0200Wa 0000136794 | yes | AllplanAttributes - Object Layer Attributes #1, WallCommon, Außenliegend: no; Object Layer Attributes #1, WallCommon, U-Wert: 0
reinforced - bearing | Architektur (TB 200-209) | concrete 0.05 m | reinforced - bearing | 0200HWa0000136791 | Betonarbeiten | concrete | C | 0200Wa 0000136796 | yes | AllplanAttributes - Object Layer Attributes #1, WallCommon, Außenliegend: no; Object Layer Attributes #1, WallCommon, U-Wert: 0
reinforced - bearing | Architektur (TB 200-209) | concrete 0.05 m | reinforced - bearing | 0200HWa0000136818 | Betonarbeiten | concrete | C | 0200Wa 0000136829 | yes | AllplanAttributes - Object Layer Attributes #1, WallCommon, Außenliegend: no; Object Layer Attributes #1, WallCommon, U-Wert: 0
reinforced - bearing | Architektur (TB 200-209) | concrete 0.05 m | reinforced - bearing | 0200HWa0000136820 | Betonarbeiten | concrete | C | 0200Wa 0000136830 | yes | AllplanAttributes - Object Layer Attributes #1, WallCommon, Außenliegend: no; Object Layer Attributes #1, WallCommon, U-Wert: 0
reinforced - bearing | Architektur (TB 200-209) | concrete 0.05 m | reinforced - bearing | 0200HWa0000136824 | Betonarbeiten | concrete | C | 0200Wa 0000136828 | yes | AllplanAttributes - Object Layer Attributes #1, WallCommon, Außenliegend: no; Object Layer Attributes #1, WallCommon, U-Wert: 0
reinforced - bearing | Architektur (TB 200-209) | concrete 0.05 m | reinforced - bearing | 0200HWa0000136552 | Betonarbeiten | concrete | C | 0200Wa 0000136556 | yes | AllplanAttributes - Object Layer Attributes #1, WallCommon, Außenliegend: no; Object Layer Attributes #1, WallCommon, U-Wert: 0
reinforced - bearing | Architektur (TB 200-209) | concrete 0.05 m | reinforced - bearing | 0200HWa0000136751 | Betonarbeiten | concrete | C | 0200Wa 0000136753 | yes | AllplanAttributes - Object Layer Attributes #1, WallCommon, Außenliegend: no; Object Layer Attributes #1, WallCommon, U-Wert: 0
reinforced - bearing | Architektur (TB 200-209) | concrete 0.05 m | reinforced - bearing | 0200HWa0000136789 | Betonarbeiten | concrete | C | 0200Wa 0000136797 | yes | AllplanAttributes - Object Layer Attributes #1, WallCommon, Außenliegend: no; Object Layer Attributes #1, WallCommon, U-Wert: 0
reinforced - bearing | Architektur (TB 200-209) | concrete 0.26 m | reinforced - bearing | 0200HWa0000000092 | Betonarbeiten | concrete | C | 0200Wa 0000000093 | yes | AllplanAttributes - Object Layer Attributes #1, Bezeichnung: concrete reinforced load-bearing; Object Layer Attributes #1, WallCommon, Tragendes Bauteil: yes
reinforced - bearing | Architektur (TB 200-209) | concrete 0.26 m | reinforced - bearing | 0200HWa0000140798 | Betonarbeiten | concrete | C | 0200Wa 0000140800 | yes | AllplanAttributes - Object Layer Attributes #1, Bezeichnung: concrete reinforced load-bearing; Object Layer Attributes #1, WallCommon, Tragendes Bauteil: yes
reinforced - bearing | Architektur (TB 200-209) | concrete 0.4 m | reinforced - bearing | 0200HWa0000031199 | Betonarbeiten | concrete | C | 0200Wa 0000031210 | yes | AllplanAttributes - Object Layer Attributes #1, WallCommon, Tragendes Bauteil: no
reinforced - bearing | Architektur (TB 200-209) | concrete 0.4 m | reinforced - bearing | 0200HWa0000000269 | Betonarbeiten | concrete | C | 0200Wa 0000000270 | yes | AllplanAttributes - Object Layer Attributes #1, WallCommon, Tragendes Bauteil: no
masonry load-bearing | Architektur (TB 200-209) | masonry 0.12 m | masonry load-bearing | 0200HWa0000001397 | Mauerarbeiten | masonry |  | 0200Wa 0000001398 | no | AllplanAttributes - Object Layer Attributes #1, Bezeichnung: masonry; Object Layer Attributes #1, Material Architektur: ma; Object Layer Attributes #1, WallCommon, Tragendes Bauteil: yes
masonry load-bearing | Architektur (TB 200-209) | masonry 0.26 m | masonry load-bearing | 0200HWa0000001226 | Mauerarbeiten | masonry |  | 0200Wa 0000001227 | no | AllplanAttributes - Object Layer Attributes #1, Bezeichnung: masonry; Object Layer Attributes #1, Material Architektur: ma; Object Layer Attributes #1, WallCommon, Tragendes Bauteil: yes
masonry load-bearing | Architektur (TB 200-209) | masonry 0.15 m | masonry load-bearing | 0200HWa0000001299 | Mauerarbeiten | masonry |  | 0200Wa 0000001300 | no | AllplanAttributes - Object Layer Attributes #1, Bezeichnung: masonry; Object Layer Attributes #1, Material Architektur: ma; Object Layer Attributes #1, WallCommon, Tragendes Bauteil: yes
masonry load-bearing | Architektur (TB 200-209) | masonry 0.34 m | masonry load-bearing | 0200HWa0000001729 | Mauerarbeiten | masonry |  | 0200Wa 0000001730 | no | AllplanAttributes - Object Layer Attributes #1, WallCommon, Außenliegend: no; Object Layer Attributes #1, WallCommon, U-Wert: 0
masonry load-bearing | Architektur (TB 200-209) | masonry 0.13 m | masonry load-bearing | 0200HWa0000001309 | Mauerarbeiten | masonry |  | 0200Wa 0000001310 | no | AllplanAttributes - Object Layer Attributes #1, Bezeichnung: masonry; Object Layer Attributes #1, Material Architektur: ma; Object Layer Attributes #1, WallCommon, Tragendes Bauteil: yes
masonry load-bearing | Architektur (TB 200-209) | masonry 0.15 m | masonry load-bearing | 0200HWa0000144124 | Mauerarbeiten | masonry |  | 0200Wa 0000144127 | no | AllplanAttributes - Object Layer Attributes #1, Bezeichnung: masonry; Object Layer Attributes #1, Material Architektur: ma; Object Layer Attributes #1, WallCommon, Tragendes Bauteil: yes
masonry load-bearing | Architektur (TB 200-209) | masonry 0.12 m | masonry load-bearing | 0200HWa0000144122 | Mauerarbeiten | masonry |  | 0200Wa 0000144129 | no | AllplanAttributes - Object Layer Attributes #1, Bezeichnung: masonry; Object Layer Attributes #1, Material Architektur: ma; Object Layer Attributes #1, WallCommon, Tragendes Bauteil: yes
masonry load-bearing | Architektur (TB 200-209) | masonry 0.12 m | masonry load-bearing | 0200HWa0000144119 | Mauerarbeiten | masonry |  | 0200Wa 0000144131 | no | AllplanAttributes - Object Layer Attributes #1, Bezeichnung: masonry; Object Layer Attributes #1, Material Architektur: ma; Object Layer Attributes #1, WallCommon, Tragendes Bauteil: yes
masonry load-bearing | Architektur (TB 200-209) | masonry 0.26 m | masonry load-bearing | 0200HWa0000001322 | Mauerarbeiten | masonry |  | 0200Wa 0000001323 | no | AllplanAttributes - Object Layer Attributes #1, Bezeichnung: masonry; Object Layer Attributes #1, Material Architektur: ma; Object Layer Attributes #1, WallCommon, Tragendes Bauteil: yes
reinforced - bearing | Architektur (TB 200-209) | concrete 0.12 m | reinforced - bearing | 0200HWa0000000308 | Betonarbeiten | concrete | C | 0200Wa 0000000309 | yes
reinforced - bearing | Architektur (TB 200-209) | concrete 0.12 m | reinforced - bearing | 0200HWa0000000300 | Betonarbeiten | concrete | C | 0200Wa 0000000301 | yes
reinforced - bearing | Architektur (TB 200-209) | concrete 0.12 m | reinforced - bearing | 0200HWa0000000292 | Betonarbeiten | concrete | C | 0200Wa 0000000293 | yes
reinforced - bearing | Architektur (TB 200-209) | concrete 0.12 m | reinforced - bearing | 0200HWa0000000284 | Betonarbeiten | concrete | C | 0200Wa 0000000285 | yes
reinforced - bearing | Architektur (TB 200-209) | concrete 0.12 m | reinforced - bearing | 0200HWa0000000455 | Betonarbeiten | concrete | C | 0200Wa 0000000456 | yes
reinforced - bearing | Architektur (TB 200-209) | concrete 0.12 m | reinforced - bearing | 0200HWa0000049945 | Betonarbeiten | concrete | C | 0200Wa 0000049946 | yes
reinforced - bearing | Architektur (TB 200-209) | concrete 0.12 m | reinforced - bearing | 0200HWa0000057040 | Betonarbeiten | concrete | C | 0200Wa 0000057043 | yes
reinforced - bearing | Architektur (TB 200-209) | concrete 0.12 m | reinforced - bearing | 0200HWa0000057076 | Betonarbeiten | concrete | C | 0200Wa 0000057079 | yes
reinforced - bearing | Architektur (TB 200-209) | concrete 0.12 m | reinforced - bearing | 0200HWa0000057112 | Betonarbeiten | concrete | C | 0200Wa 0000057115 | yes
reinforced - bearing | Architektur (TB 200-209) | concrete 0.12 m | reinforced - bearing | 0200HWa0000057192 | Betonarbeiten | concrete | C | 0200Wa 0000057195 | yes
reinforced - bearing | Architektur (TB 200-209) | concrete 0.02 m | reinforced - bearing | 0200HWa0000134935 | Betonarbeiten | concrete | C | 0200Wa 0000134936 | yes | AllplanAttributes - Object Layer Attributes #1, WallCommon, Außenliegend: no; Object Layer Attributes #1, WallCommon, U-Wert: 0
reinforced - bearing | Architektur (TB 200-209) | concrete 0.02 m | reinforced - bearing | 0200HWa0000134953 | Betonarbeiten | concrete | C | 0200Wa 0000134954 | yes | AllplanAttributes - Object Layer Attributes #1, WallCommon, Außenliegend: no; Object Layer Attributes #1, WallCommon, U-Wert: 0
reinforced - bearing | Architektur (TB 200-209) | concrete 0.02 m | reinforced - bearing | 0200HWa0000134974 | Betonarbeiten | concrete | C | 0200Wa 0000134975 | yes | AllplanAttributes - Object Layer Attributes #1, WallCommon, Außenliegend: no; Object Layer Attributes #1, WallCommon, U-Wert: 0
reinforced - bearing | Architektur (TB 200-209) | concrete 0.05 m | reinforced - bearing | 0200HWa0000136849 | Betonarbeiten | concrete | C | 0200Wa 0000136859 | yes | AllplanAttributes - Object Layer Attributes #1, WallCommon, Außenliegend: no; Object Layer Attributes #1, WallCommon, U-Wert: 0
reinforced - bearing | Architektur (TB 200-209) | concrete 0.05 m | reinforced - bearing | 0200HWa0000136851 | Betonarbeiten | concrete | C | 0200Wa 0000136858 | yes | AllplanAttributes - Object Layer Attributes #1, WallCommon, Außenliegend: no; Object Layer Attributes #1, WallCommon, U-Wert: 0
reinforced - bearing | Architektur (TB 200-209) | concrete 0.05 m | reinforced - bearing | 0200HWa0000136855 | Betonarbeiten | concrete | C | 0200Wa 0000136860 | yes | AllplanAttributes - Object Layer Attributes #1, WallCommon, Außenliegend: no; Object Layer Attributes #1, WallCommon, U-Wert: 0
reinforced - bearing | Architektur (TB 200-209) | concrete 0.12 m | reinforced - bearing | 0200HWa0000057285 | Betonarbeiten | concrete | C | 0200Wa 0000057288 | yes
reinforced - bearing | Architektur (TB 200-209) | concrete 0.02 m | reinforced - bearing | 0200HWa0000134919 | Betonarbeiten | concrete | C | 0200Wa 0000134920 | yes | AllplanAttributes - Object Layer Attributes #1, WallCommon, Außenliegend: no; Object Layer Attributes #1, WallCommon, U-Wert: 0
reinforced - bearing | Architektur (TB 200-209) | concrete 0.05 m | reinforced - bearing | 0200HWa0000136822 | Betonarbeiten | concrete | C | 0200Wa 0000136826 | yes | AllplanAttributes - Object Layer Attributes #1, WallCommon, Außenliegend: no; Object Layer Attributes #1, WallCommon, U-Wert: 0
reinforced - bearing | Architektur (TB 200-209) | concrete 0.05 m | reinforced - bearing | 0200HWa0000137658 | Betonarbeiten | concrete | C | 0200Wa 0000137660 | yes | AllplanAttributes - Object Layer Attributes #1, WallCommon, Außenliegend: no; Object Layer Attributes #1, WallCommon, U-Wert: 0
reinforced - bearing | Architektur (TB 200-209) | concrete 0.02 m | reinforced - bearing | 0200HWa0000129562 | Betonarbeiten | concrete | C | 0200Wa 0000129563 | yes | AllplanAttributes - Object Layer Attributes #1, WallCommon, Außenliegend: no; Object Layer Attributes #1, WallCommon, U-Wert: 0
reinforced - bearing | Architektur (TB 200-209) | concrete 0.37 m | reinforced - bearing | 0200HWa0000144870 | Betonarbeiten | concrete | C | 0200Wa 0000144880 | yes
reinforced - bearing | Architektur (TB 200-209) | concrete 0.37 m | reinforced - bearing | 0200HWa0000127669 | Betonarbeiten | concrete | C | 0200Wa 0000127681 | yes
reinforced - bearing | Architektur (TB 200-209) | concrete 0.26 m | reinforced - bearing | 0200HWa0000140834 | Betonarbeiten | concrete | C | 0200Wa 0000140836 | yes | AllplanAttributes - Object Layer Attributes #1, Bezeichnung: concrete reinforced load-bearing; Object Layer Attributes #1, WallCommon, Tragendes Bauteil: yes
reinforced - bearing | Architektur (TB 200-209) | concrete 0.39 m | reinforced - bearing | 0200HWa0000130533 | Betonarbeiten | concrete | C | 0200Wa 0000130554 | yes | AllplanAttributes - Object Layer Attributes #1, Bezeichnung: concrete reinforced load-bearing; Object Layer Attributes #1, WallCommon, Tragendes Bauteil: yes
reinforced - bearing | Architektur (TB 200-209) | concrete 0.39 m | reinforced - bearing | 0200HWa0000000058 | Betonarbeiten | concrete | C | 0200Wa 0000000059 | yes | AllplanAttributes - Object Layer Attributes #1, Bezeichnung: concrete reinforced load-bearing; Object Layer Attributes #1, WallCommon, Tragendes Bauteil: yes
reinforced - bearing | Architektur (TB 200-209) | concrete 0.02 m | reinforced - bearing | 0200HWa0000129573 | Betonarbeiten | concrete | C | 0200Wa 0000129574 | yes | AllplanAttributes - Object Layer Attributes #1, WallCommon, Außenliegend: no; Object Layer Attributes #1, WallCommon, U-Wert: 0
reinforced - bearing | Architektur (TB 200-209) | concrete 0.05 m | reinforced - bearing | 0200HWa0000136853 | Betonarbeiten | concrete | C | 0200Wa 0000136861 | yes | AllplanAttributes - Object Layer Attributes #1, WallCommon, Außenliegend: no; Object Layer Attributes #1, WallCommon, U-Wert: 0
reinforced - bearing | Architektur (TB 200-209) | concrete 0.02 m | reinforced - bearing | 0200HWa0000156801 | Betonarbeiten | concrete | C | 0200Wa 0000156803 | yes | AllplanAttributes - Object Layer Attributes #1, WallCommon, Außenliegend: no; Object Layer Attributes #1, WallCommon, U-Wert: 0
reinforced - bearing | Architektur (TB 200-209) | concrete 0.12 m | reinforced - bearing | 0200HWa0000000176 | Betonarbeiten | concrete | C | 0200Wa 0000000177 | yes
reinforced - bearing | Architektur (TB 200-209) | concrete 0.12 m | reinforced - bearing | 0200HWa0000059618 | Betonarbeiten | concrete | C | 0200Wa 0000059620 | yes | AllplanAttributes - Object Layer Attributes #1, WallCommon, Außenliegend: no; Object Layer Attributes #1, WallCommon, U-Wert: 0
reinforced - bearing | Architektur (TB 200-209) | concrete 0.12 m | reinforced - bearing | 0200HWa0000059236 | Betonarbeiten | concrete | C | 0200Wa 0000059238 | yes | AllplanAttributes - Object Layer Attributes #1, WallCommon, Außenliegend: no; Object Layer Attributes #1, WallCommon, U-Wert: 0
reinforced - bearing | Architektur (TB 200-209) | concrete 0.12 m | reinforced - bearing | 0200HWa0000056347 | Betonarbeiten | concrete | C | 0200Wa 0000056348 | yes | AllplanAttributes - Object Layer Attributes #1, WallCommon, Außenliegend: no; Object Layer Attributes #1, WallCommon, U-Wert: 0
reinforced - bearing | Architektur (TB 200-209) | concrete 0.51 m, layer 0.16 m, layer 0.16 m | reinforced - bearing | 0200HWa0000000026 | Betonarbeiten | concrete | C | 0200Wa 0000000027 | yes | AllplanAttributes - Object Layer Attributes #1, Bezeichnung: concrete reinforced load-bearing; Object Layer Attributes #1, WallCommon, Tragendes Bauteil: yes; Object Layer Attributes #2, Gewerk: Wärmedämm-Verbundsysteme; Object Layer Attributes #2, Allright_Bauteil_ID: 0200Wa 0000165909; Object Layer Attributes #2, Abrechnungsart: m²; Object Layer Attributes #2, Objektname: Wand; Object Layer Attributes #2, WallCommon, Status: Neubau; Object Layer Attributes #2, WallCommon, Tragendes Bauteil: no; Object Layer Attributes #2, WallCommon, Brennbares Material: no; Object Layer Attributes #2, WallCommon, Brandabschnittsdefinierendes Bauteil: no; Object Layer Attributes #2, WallCommon, Raumhohe Wand: yes; Object Layer Attributes #3, Allright_Bauteil_ID: 0200Wa 0000165910; Object Layer Attributes #3, Abrechnungsart: m²; Object Layer Attributes #3, Objektname: Wand; Object Layer Attributes #3, WallCommon, Status: Neubau; Object Layer Attributes #3, WallCommon, Tragendes Bauteil: no; Object Layer Attributes #3, WallCommon, Brennbares Material: no; Object Layer Attributes #3, WallCommon, Brandabschnittsdefinierendes Bauteil: no; Object Layer Attributes #3, WallCommon, Raumhohe Wand: yes
reinforced - bearing | Architektur (TB 250-259) | concrete 0.4 m | reinforced - bearing | 0250HWa0000008892 | Betonarbeiten | concrete | C | 0250Wa 0000008992 | yes | AllplanAttributes - Object Layer Attributes #1, WallCommon, Tragendes Bauteil: no
reinforced - bearing | Architektur (TB 250-259) | concrete 0.25 m | reinforced - bearing | 0250HWa0000008894 | Betonarbeiten | concrete | C | 0250Wa 0000009006 | yes | AllplanAttributes - Object Layer Attributes #1, Bezeichnung: concrete reinforced load-bearing; Object Layer Attributes #1, WallCommon, Tragendes Bauteil: yes
reinforced - bearing | Architektur (TB 250-259) | concrete 0.4 m | reinforced - bearing | 0250HWa0000008845 | Betonarbeiten | concrete | C | 0250Wa 0000008994 | yes | AllplanAttributes - Object Layer Attributes #1, WallCommon, Tragendes Bauteil: no
masonry load-bearing | Architektur (TB 250-259) | masonry 0.12 m | masonry load-bearing | 0250HWa0000009673 | Mauerarbeiten | masonry |  | 0250Wa 0000009730 | no | AllplanAttributes - Object Layer Attributes #1, Bezeichnung: masonry; Object Layer Attributes #1, Material Architektur: ma; Object Layer Attributes #1, WallCommon, Tragendes Bauteil: yes
masonry load-bearing | Architektur (TB 250-259) | masonry 0.15 m | masonry load-bearing | 0250HWa0000009453 | Mauerarbeiten | masonry |  | 0250Wa 0000009493 | no | AllplanAttributes - Object Layer Attributes #1, Bezeichnung: masonry; Object Layer Attributes #1, Material Architektur: ma; Object Layer Attributes #1, WallCommon, Tragendes Bauteil: yes
masonry load-bearing | Architektur (TB 250-259) | masonry 0.12 m | masonry load-bearing | 0250HWa0000009456 | Mauerarbeiten | masonry |  | 0250Wa 0000009480 | no | AllplanAttributes - Object Layer Attributes #1, Bezeichnung: masonry; Object Layer Attributes #1, Material Architektur: ma; Object Layer Attributes #1, WallCommon, Tragendes Bauteil: yes
masonry load-bearing | Architektur (TB 250-259) | masonry 0.12 m | masonry load-bearing | 0250HWa0000009458 | Mauerarbeiten | masonry |  | 0250Wa 0000009495 | no | AllplanAttributes - Object Layer Attributes #1, Bezeichnung: masonry; Object Layer Attributes #1, Material Architektur: ma; Object Layer Attributes #1, WallCommon, Tragendes Bauteil: yes
masonry load-bearing | Architektur (TB 250-259) | masonry 0.4 m | masonry load-bearing | 0250HWa0000002725 | Mauerarbeiten | masonry |  | 0250Wa 0000002735 | no | AllplanAttributes - Object Layer Attributes #1, Bezeichnung: masonry; Object Layer Attributes #1, Material Architektur: ma; Object Layer Attributes #1, WallCommon, Tragendes Bauteil: yes
masonry load-bearing | Architektur (TB 250-259) | masonry 0.26 m | masonry load-bearing | 0250HWa0000009672 | Mauerarbeiten | masonry |  | 0250Wa 0000009726 | no | AllplanAttributes - Object Layer Attributes #1, Bezeichnung: masonry; Object Layer Attributes #1, Material Architektur: ma; Object Layer Attributes #1, WallCommon, Tragendes Bauteil: yes
masonry load-bearing | Architektur (TB 250-259) | masonry 0.12 m | masonry load-bearing | 0250HWa0000009714 | Mauerarbeiten | masonry |  | 0250Wa 0000009722 | no | AllplanAttributes - Object Layer Attributes #1, Bezeichnung: masonry; Object Layer Attributes #1, Material Architektur: ma; Object Layer Attributes #1, WallCommon, Tragendes Bauteil: yes
masonry load-bearing | Architektur (TB 250-259) | masonry 0.13 m | masonry load-bearing | 0250HWa0000009689 | Mauerarbeiten | masonry |  | 0250Wa 0000009738 | no | AllplanAttributes - Object Layer Attributes #1, Bezeichnung: masonry; Object Layer Attributes #1, Material Architektur: ma; Object Layer Attributes #1, WallCommon, Tragendes Bauteil: yes
masonry load-bearing | Architektur (TB 250-259) | masonry 0.15 m | masonry load-bearing | 0250HWa0000009691 | Mauerarbeiten | masonry |  | 0250Wa 0000009734 | no | AllplanAttributes - Object Layer Attributes #1, Bezeichnung: masonry; Object Layer Attributes #1, Material Architektur: ma; Object Layer Attributes #1, WallCommon, Tragendes Bauteil: yes
reinforced - bearing | Architektur (TB 250-259) | concrete 0.26 m | reinforced - bearing | 0250HWa0000009383 | Betonarbeiten | concrete | C | 0250Wa 0000009385 | yes | AllplanAttributes - Object Layer Attributes #1, Bezeichnung: concrete reinforced load-bearing; Object Layer Attributes #1, WallCommon, Tragendes Bauteil: yes
reinforced - bearing | Architektur (TB 250-259) | concrete 0.51 m | reinforced - bearing | 0250HWa0000004285 | Betonarbeiten | concrete | C | 0250Wa 0000004286 | yes | AllplanAttributes - Object Layer Attributes #1, Bezeichnung: concrete reinforced load-bearing; Object Layer Attributes #1, WallCommon, Tragendes Bauteil: yes
reinforced - bearing | Architektur (TB 250-259) | concrete 0.4 m | reinforced - bearing | 0250HWa0000023176 | Betonarbeiten | concrete | C | 0250Wa 0000023181 | yes | AllplanAttributes - Object Layer Attributes #1, WallCommon, Tragendes Bauteil: no
masonry load-bearing | Architektur (TB 250-259) | masonry 0.26 m | masonry load-bearing | 0250HWa0000002643 | Mauerarbeiten | masonry |  | 0250Wa 0000002776 | no | AllplanAttributes - Object Layer Attributes #1, Bezeichnung: masonry; Object Layer Attributes #1, Material Architektur: ma; Object Layer Attributes #1, WallCommon, Tragendes Bauteil: yes
reinforced - bearing | Architektur (TB 250-259) | concrete 0.26 m | reinforced - bearing | 0250HWa0000002637 | Betonarbeiten | concrete | C | 0250Wa 0000002737 | yes | AllplanAttributes - Object Layer Attributes #1, Bezeichnung: concrete reinforced load-bearing; Object Layer Attributes #1, WallCommon, Tragendes Bauteil: yes
reinforced - bearing | Architektur (TB 250-259) | concrete 0.39 m | reinforced - bearing | 0250HWa0000002663 | Betonarbeiten | concrete | C | 0250Wa 0000002801 | yes | AllplanAttributes - Object Layer Attributes #1, Bezeichnung: concrete reinforced load-bearing; Object Layer Attributes #1, WallCommon, Tragendes Bauteil: yes
reinforced - bearing | Architektur (TB 250-259) | concrete 0.12 m | reinforced - bearing | 0250HWa0000025062 | Betonarbeiten | concrete | C | 0250Wa 0000025063 | yes
reinforced - bearing | Architektur (TB 250-259) | concrete 0.25 m | reinforced - bearing | 0250HWa0000024501 | Betonarbeiten | concrete | C | 0250Wa 0000024524 | yes
reinforced - bearing | Architektur (TB 250-259) | concrete 0.12 m | reinforced - bearing | 0250HWa0000008715 | Betonarbeiten | concrete | C | 0250Wa 0000008718 | yes
reinforced - bearing | Architektur (TB 250-259) | concrete 0.12 m | reinforced - bearing | 0250HWa0000025113 | Betonarbeiten | concrete | C | 0250Wa 0000025115 | yes
reinforced - bearing | Architektur (TB 250-259) | concrete 0.36 m | reinforced - bearing | 0250HWa0000008843 | Betonarbeiten | concrete | C | 0250Wa 0000008928 | yes | AllplanAttributes - Object Layer Attributes #1, Bezeichnung: concrete reinforced load-bearing; Object Layer Attributes #1, WallCommon, Tragendes Bauteil: yes
reinforced - bearing | Architektur (TB 250-259) | concrete 0.12 m | reinforced - bearing | 0250HWa0000015521 | Betonarbeiten | concrete | C | 0250Wa 0000015526 | yes | AllplanAttributes - Object Layer Attributes #1, WallCommon, Außenliegend: no; Object Layer Attributes #1, WallCommon, U-Wert: 0
reinforced - bearing | Architektur (TB 250-259) | concrete 0.12 m | reinforced - bearing | 0250HWa0000015523 | Betonarbeiten | concrete | C | 0250Wa 0000015528 | yes | AllplanAttributes - Object Layer Attributes #1, WallCommon, Außenliegend: no; Object Layer Attributes #1, WallCommon, U-Wert: 0
reinforced - bearing | Architektur (TB 250-259) | concrete 0.12 m | reinforced - bearing | 0250HWa0000008713 | Betonarbeiten | concrete | C | 0250Wa 0000008720 | yes
reinforced - bearing | Architektur (TB 250-259) | concrete 0.25 m | reinforced - bearing | 0250HWa0000017486 | Betonarbeiten | concrete | C | 0250Wa 0000017489 | yes
reinforced - bearing | Architektur (TB 250-259) | concrete 0.37 m | reinforced - bearing | 0250HWa0000004422 | Betonarbeiten | concrete | C | 0250Wa 0000004424 | yes
reinforced - bearing | Architektur (TB 450-459) | concrete 0.39 m | reinforced - bearing | 0450HWa0000000059 | Betonarbeiten | concrete | C | 0450Wa 0000000092 | yes | AllplanAttributes - Object Layer Attributes #1, Bezeichnung: concrete reinforced load-bearing; Object Layer Attributes #1, WallCommon, Tragendes Bauteil: yes
reinforced - bearing | Architektur (TB 450-459) | concrete 0.26 m | reinforced - bearing | 0450HWa0000000473 | Betonarbeiten | concrete | C | 0450Wa 0000000474 | yes | AllplanAttributes - Object Layer Attributes #1, Bezeichnung: concrete reinforced load-bearing; Object Layer Attributes #1, WallCommon, Tragendes Bauteil: yes
masonry load-bearing | Architektur (TB 450-459) | masonry 0.12 m | masonry load-bearing | 0450HWa0000016306 | Mauerarbeiten | masonry |  | 0450Wa 0000016345 | no | AllplanAttributes - Object Layer Attributes #1, Bezeichnung: masonry; Object Layer Attributes #1, Material Architektur: ma; Object Layer Attributes #1, WallCommon, Tragendes Bauteil: yes
masonry load-bearing | Architektur (TB 450-459) | masonry 0.12 m | masonry load-bearing | 0450HWa0000016312 | Mauerarbeiten | masonry |  | 0450Wa 0000016336 | no | AllplanAttributes - Object Layer Attributes #1, Bezeichnung: masonry; Object Layer Attributes #1, Material Architektur: ma; Object Layer Attributes #1, WallCommon, Tragendes Bauteil: yes
masonry load-bearing | Architektur (TB 450-459) | masonry 0.27 m | masonry load-bearing | 0450HWa0000016321 | Mauerarbeiten | masonry |  | 0450Wa 0000016334 | no | AllplanAttributes - Object Layer Attributes #1, Bezeichnung: masonry; Object Layer Attributes #1, Material Architektur: ma; Object Layer Attributes #1, WallCommon, Tragendes Bauteil: yes
masonry load-bearing | Architektur (TB 450-459) | masonry 0.12 m | masonry load-bearing | 0450HWa0000016324 | Mauerarbeiten | masonry |  | 0450Wa 0000016330 | no | AllplanAttributes - Object Layer Attributes #1, Bezeichnung: masonry; Object Layer Attributes #1, Material Architektur: ma; Object Layer Attributes #1, WallCommon, Tragendes Bauteil: yes
masonry load-bearing | Architektur (TB 450-459) | masonry 0.12 m | masonry load-bearing | 0450HWa0000016326 | Mauerarbeiten | masonry |  | 0450Wa 0000016332 | no | AllplanAttributes - Object Layer Attributes #1, Bezeichnung: masonry; Object Layer Attributes #1, Material Architektur: ma; Object Layer Attributes #1, WallCommon, Tragendes Bauteil: yes
reinforced - bearing | Architektur (TB 450-459) | concrete 0.12 m | reinforced - bearing | 0450HWa0000039700 | Betonarbeiten | concrete | C | 0450Wa 0000039703 | yes
reinforced - bearing | Architektur (TB 450-459) | concrete 0.12 m | reinforced - bearing | 0450HWa0000039696 | Betonarbeiten | concrete | C | 0450Wa 0000039699 | yes
reinforced - bearing | Architektur (TB 450-459) | concrete 0.4 m | reinforced - bearing | 0450HWa0000000037 | Betonarbeiten | concrete | C | 0450Wa 0000000046 | yes | AllplanAttributes - Object Layer Attributes #1, WallCommon, Tragendes Bauteil: no
reinforced - bearing | Architektur (TB 450-459) | concrete 0.37 m | reinforced - bearing | 0450HWa0000000043 | Betonarbeiten | concrete | C | 0450Wa 0000000122 | yes
reinforced - bearing | Architektur (TB 450-459) | concrete 0.4 m | reinforced - bearing | 0450HWa0000062056 | Betonarbeiten | concrete | C | 0450Wa 0000062062 | yes | AllplanAttributes - Object Layer Attributes #1, WallCommon, Tragendes Bauteil: no
reinforced - bearing | Architektur (TB 450-459) | concrete 0.4 m | reinforced - bearing | 0450HWa0000061717 | Betonarbeiten | concrete | C | 0450Wa 0000061725 | yes | AllplanAttributes - Object Layer Attributes #1, WallCommon, Tragendes Bauteil: no
reinforced - bearing | Architektur (TB 450-459) | concrete 0.4 m | reinforced - bearing | 0450HWa0000062423 | Betonarbeiten | concrete | C | 0450Wa 0000062428 | yes | AllplanAttributes - Object Layer Attributes #1, WallCommon, Tragendes Bauteil: no
reinforced - bearing | Architektur (TB 450-459) | concrete 0.4 m | reinforced - bearing | 0450HWa0000062425 | Betonarbeiten | concrete | C | 0450Wa 0000062430 | yes | AllplanAttributes - Object Layer Attributes #1, WallCommon, Tragendes Bauteil: no
masonry load-bearing | Architektur (TB 450-459) | masonry 0.1 m | masonry load-bearing | 0450HWa0000062438 | Mauerarbeiten | masonry |  | 0450Wa 0000062440 | no | AllplanAttributes - Object Layer Attributes #1, Bezeichnung: masonry; Object Layer Attributes #1, Material Architektur: ma; Object Layer Attributes #1, WallCommon, Tragendes Bauteil: yes
masonry load-bearing | Architektur (TB 450-459) | masonry 0.1 m | masonry load-bearing | 0450HWa0000016305 | Mauerarbeiten | masonry |  | 0450Wa 0000016352 | no | AllplanAttributes - Object Layer Attributes #1, Bezeichnung: masonry; Object Layer Attributes #1, Material Architektur: ma; Object Layer Attributes #1, WallCommon, Tragendes Bauteil: yes
masonry load-bearing | Architektur (TB 450-459) | masonry 0.12 m | masonry load-bearing | 0450HWa0000062486 | Mauerarbeiten | masonry |  | 0450Wa 0000062493 | no | AllplanAttributes - Object Layer Attributes #1, Bezeichnung: masonry; Object Layer Attributes #1, Material Architektur: ma; Object Layer Attributes #1, WallCommon, Tragendes Bauteil: yes
masonry load-bearing | Architektur (TB 450-459) | masonry 0.12 m | masonry load-bearing | 0450HWa0000016314 | Mauerarbeiten | masonry |  | 0450Wa 0000016357 | no | AllplanAttributes - Object Layer Attributes #1, Bezeichnung: masonry; Object Layer Attributes #1, Material Architektur: ma; Object Layer Attributes #1, WallCommon, Tragendes Bauteil: yes

# IfcWindow (37)
PartitioningType: USERDEFINED
Name | In | OverallHeight (m) | OverallWidth (m) | PredefinedType | AllplanAttributes (Window), V6 (m) = AllplanAttributes (Window), V7 (m) = AllplanAttributes (Window), V8 (m) = AllplanAttributes (Window), V9 = HeightWindowSillInside = OffsetOpeningBottom = OffsetOpeningTop = OffsetOpeningLeft = OffsetOpeningRight = ThermalTransmittance (W/K/m2) = Infiltration (m3/hour/m) | AllplanAttributes (Window), Programmversion | AllplanAttributes (Window), Bezeichnung = Attributset-Objekt | AllplanAttributes (Window), Plugin_Bezeichnung | AllplanAttributes (Window), Plugin_Objektname | Glasanteil_berücksichtigen | AllplanAttributes (Window), Version | AllplanAttributes (Window), Allright_Bauteil_ID | AllplanAttributes (Window), Abrechnungsart | AllplanAttributes (Window), Objektname | GlassSurface | HeightWindowSillOutside | DeductionOpeningBottom | DeductionOpeningLeft = DeductionOpeningRight = DeductionOpeningTop | Status | IsExternal = SmokeStop = FireExit | HasDrive = HasSillExternal = HasSillInternal
Window | Architektur (TB 200-209) | 1 | 0.36 | WINDOW | 0 | 3.0 | Window | MainObject | SmartPartCompressed | 100 | 8.0 | 0200Mak0000165129 | St | Fenstermakro, -SmartPart | 0.2001 | 0 | 50 | 50 | NEW | no | yes
Window | Architektur (TB 200-209) | 3.42 | 1.79643 | WINDOW | 0 | 3.0 | Window | MainObject | SmartPartCompressed | 100 | 7.0 | 0200Mak0000040522 | St | Fenstermakro, -SmartPart | 4.27823 | 50 | 140 | 50 | NEW | no | yes
Window | Architektur (TB 200-209) | 3.42 | 1.79643 | WINDOW | 0 | 3.0 | Window | MainObject | SmartPartCompressed | 100 | 7.0 | 0200Mak0000041857 | St | Fenstermakro, -SmartPart | 4.27823 | 50 | 140 | 50 | NEW | no | yes
Window | Architektur (TB 200-209) | 3.42 | 1.79643 | WINDOW | 0 | 3.0 | Window | MainObject | SmartPartCompressed | 100 | 7.0 | 0200Mak0000041869 | St | Fenstermakro, -SmartPart | 4.27823 | 50 | 140 | 50 | NEW | no | yes
Window | Architektur (TB 200-209) | 1.65 | 1.8 | WINDOW | 0 | 3.0 | Window | MainObject | SmartPartCompressed | 100 | 7.0 | 0200Mak0000042187 | St | Fenstermakro, -SmartPart | 2.02541 | 50 | 50 | 50 | NEW | no | yes
Window | Architektur (TB 200-209) | 2.35 | 1.22 | WINDOW | 0 | 3.0 | Window | MainObject | SmartPartCompressed | 100 | 7.0 | 0200Mak0000039377 | St | Fenstermakro, -SmartPart | 1.8661 | 50 | 70 | 50 | NEW | no | yes
Window | Architektur (TB 200-209) | 2.35 | 1.22 | WINDOW | 0 | 3.0 | Window | MainObject | SmartPartCompressed | 100 | 7.0 | 0200Mak0000039311 | St | Fenstermakro, -SmartPart | 1.8661 | 50 | 70 | 50 | NEW | no | yes
Window | Architektur (TB 200-209) | 2.35 | 1.22 | WINDOW | 0 | 3.0 | Window | MainObject | SmartPartCompressed | 100 | 7.0 | 0200Mak0000038990 | St | Fenstermakro, -SmartPart | 1.8661 | 50 | 70 | 50 | NEW | no | yes
Window | Architektur (TB 200-209) | 2.65 | 1.5 | WINDOW | 0 | 3.0 | Window | MainObject | SmartPartCompressed | 100 | 7.0 | 0200Mak0000044424 | St | Fenstermakro, -SmartPart | 2.72636 | 50 | 100 | 100 | NEW | no | yes
Window | Architektur (TB 200-209) | 0.35 | 0.35 | WINDOW | 0 | 3.0 | Window | MainObject | SmartPartCompressed | 100 | 8.0 | 0200Mak0000137141 | St | Fenstermakro, -SmartPart | 0.0643964 | 0 | 20 | 20 | NEW | no | yes
Window | Architektur (TB 200-209) | 0.35 | 0.35 | WINDOW | 0 | 3.0 | Window | MainObject | SmartPartCompressed | 100 | 8.0 | 0200Mak0000137113 | St | Fenstermakro, -SmartPart | 0.0643964 | 0 | 20 | 20 | NEW | no | yes
Window | Architektur (TB 200-209) | 0.35 | 0.35 | WINDOW | 0 | 3.0 | Window | MainObject | SmartPartCompressed | 100 | 8.0 | 0200Mak0000137120 | St | Fenstermakro, -SmartPart | 0.0643964 | 0 | 20 | 20 | NEW | no | yes
Window | Architektur (TB 200-209) | 0.35 | 0.35 | WINDOW | 0 | 3.0 | Window | MainObject | SmartPartCompressed | 100 | 8.0 | 0200Mak0000137127 | St | Fenstermakro, -SmartPart | 0.0643964 | 0 | 20 | 20 | NEW | no | yes
Window | Architektur (TB 200-209) | 1.12 | 1.35 | WINDOW | 0 | 3.0 | Window | MainObject | SmartPartCompressed | 100 | 8.0 | 0200Mak0000053635 | St | Fenstermakro, -SmartPart | 1.071 | 0 | 50 | 50 | NEW | no | yes
Window | Architektur (TB 200-209) | 0.35 | 0.35 | WINDOW | 0 | 3.0 | Window | MainObject | SmartPartCompressed | 100 | 8.0 | 0200Mak0000137134 | St | Fenstermakro, -SmartPart | 0.0643964 | 0 | 20 | 20 | NEW | no | yes
Window | Architektur (TB 200-209) | 2.45 | 1.3 | WINDOW | 0 | 3.0 | Window | MainObject | SmartPartCompressed | 100 | 7.0 | 0200Mak0000038636 | St | Fenstermakro, -SmartPart | 2.06718 | 50 | 70 | 50 | NEW | no | yes
Window | Architektur (TB 200-209) | 2.45 | 1.3 | WINDOW | 0 | 3.0 | Window | MainObject | SmartPartCompressed | 100 | 7.0 | 0200Mak0000034646 | St | Fenstermakro, -SmartPart | 2.06718 | 50 | 70 | 50 | NEW | no | yes
Window | Architektur (TB 200-209) | 0.3 | 0.51664 | WINDOW | 0 | 3.0 | Window | MainObject | SmartPartCompressed | 100 | 8.0 | 0200Mak0000156869 | St | Fenstermakro, -SmartPart | 0.0601013 | 0 | 30 | 30 | NEW | no | yes
Window | Architektur (TB 200-209) | 1.8 | 1.8 | WINDOW | 0 | 3.0 | Window | MainObject | SmartPartCompressed | 100 | 7.0 | 0200Mak0000016848 | St | Fenstermakro, -SmartPart | 1.60439 | 0 | 100 | 100 | NEW | no | yes
Window | Architektur (TB 200-209) | 1.8 | 1.8 | WINDOW | 0 | 3.0 | Window | MainObject | SmartPartCompressed | 100 | 7.0 | 0200Mak0000018086 | St | Fenstermakro, -SmartPart | 1.60439 | 0 | 100 | 100 | NEW | no | yes
Window | Architektur (TB 200-209) | 1.8 | 1.8 | WINDOW | 0 | 3.0 | Window | MainObject | SmartPartCompressed | 100 | 7.0 | 0200Mak0000018074 | St | Fenstermakro, -SmartPart | 1.60439 | 0 | 100 | 100 | NEW | no | yes
Window | Architektur (TB 200-209) | 1.8 | 1.8 | WINDOW | 0 | 3.0 | Window | MainObject | SmartPartCompressed | 100 | 7.0 | 0200Mak0000018062 | St | Fenstermakro, -SmartPart | 1.60439 | 0 | 100 | 100 | NEW | no | yes
Window | Architektur (TB 200-209) | 1.8 | 1.8 | WINDOW | 0 | 3.0 | Window | MainObject | SmartPartCompressed | 100 | 7.0 | 0200Mak0000018050 | St | Fenstermakro, -SmartPart | 1.60439 | 0 | 100 | 100 | NEW | no | yes
Window | Architektur (TB 250-259) | 2.4 | 1.3 | WINDOW | 0 | 3.0 | Window | MainObject | SmartPartCompressed | 100 | 7.0 | 0250Mak0000004707 | St | Fenstermakro, -SmartPart | 2.04463 | 0 | 50 | 50 | NEW | no | yes
Window | Architektur (TB 250-259) | 2.4 | 1.3 | WINDOW | 0 | 3.0 | Window | MainObject | SmartPartCompressed | 100 | 7.0 | 0250Mak0000005506 | St | Fenstermakro, -SmartPart | 2.04463 | 0 | 50 | 50 | NEW | no | yes
Window | Architektur (TB 250-259) | 2.4 | 1.3 | WINDOW | 0 | 3.0 | Window | MainObject | SmartPartCompressed | 100 | 7.0 | 0250Mak0000005546 | St | Fenstermakro, -SmartPart | 2.04463 | 0 | 50 | 50 | NEW | no | yes
Window | Architektur (TB 250-259) | 2.25 | 1.22 | WINDOW | 0 | 3.0 | Window | MainObject | SmartPartCompressed | 100 | 7.0 | 0250Mak0000024514 | St | Fenstermakro, -SmartPart | 1.74342 | 0 | 50 | 50 | NEW | no | yes
Window | Architektur (TB 250-259) | 2.25 | 1.22 | WINDOW | 0 | 3.0 | Window | MainObject | SmartPartCompressed | 100 | 7.0 | 0250Mak0000024512 | St | Fenstermakro, -SmartPart | 1.74342 | 0 | 50 | 50 | NEW | no | yes
Window | Architektur (TB 250-259) | 2.25 | 1.22 | WINDOW | 0 | 3.0 | Window | MainObject | SmartPartCompressed | 100 | 7.0 | 0250Mak0000024510 | St | Fenstermakro, -SmartPart | 1.74342 | 0 | 50 | 50 | NEW | no | yes
Window | Architektur (TB 250-259) | 0.6 | 0.5 | WINDOW | 0 | 3.0 | Window | MainObject | SmartPartCompressed | 100 | 8.0 | 0250Mak0000011203 | St | Fenstermakro, -SmartPart | 0.1739 | 0 | 50 | 50 | NEW | no | yes
Window | Architektur (TB 250-259) | 2.25 | 1.3 | WINDOW | 0 | 3.0 | Window | MainObject | SmartPartCompressed | 100 | 7.0 | 0250Mak0000031591 | St | Fenstermakro, -SmartPart | 1.89388 | 0 | 50 | 50 | NEW | no | yes
Window | Architektur (TB 250-259) | 2.25 | 1.3 | WINDOW | 0 | 3.0 | Window | MainObject | SmartPartCompressed | 100 | 7.0 | 0250Mak0000005888 | St | Fenstermakro, -SmartPart | 1.89388 | 0 | 50 | 50 | NEW | no | yes
1c white | Architektur (TB 250-259) | 1.05 | 0.65 | SKYLIGHT | AllplanAttributes (1c white) - V6: 0 m; V7: 0 m; V8: 0 m; V9: 0; Programmversion: 2.2; Bezeichnung: 1c white; Plugin_Bezeichnung: MainObject; Plugin_Objektname: SmartPartCompressed; Version: 1.0; Allright_Bauteil_ID: 0252Mak0000000038; Abrechnungsart: St; Objektname: Dachflächenfenstermakro
1c white | Architektur (TB 450-459) | 1.05 | 0.65 | SKYLIGHT | AllplanAttributes (1c white) - V6: 0 m; V7: 0 m; V8: 0 m; V9: 0; Programmversion: 2.2; Bezeichnung: 1c white; Plugin_Bezeichnung: MainObject; Plugin_Objektname: SmartPartCompressed; Version: 1.0; Allright_Bauteil_ID: 0452Mak0000000016; Abrechnungsart: St; Objektname: Dachflächenfenstermakro
1c white | Architektur (TB 450-459) | 0.55 | 0.4 | SKYLIGHT | AllplanAttributes (1c white) - V6: 0 m; V7: 0 m; V8: 0 m; V9: 0; Programmversion: 2.2; Bezeichnung: 1c white; Plugin_Bezeichnung: MainObject; Plugin_Objektname: SmartPartCompressed; Version: 1.0; Allright_Bauteil_ID: 0452Mak0000000030; Abrechnungsart: St; Objektname: Dachflächenfenstermakro
1c white | Architektur (TB 450-459) | 1.05 | 0.65 | SKYLIGHT | AllplanAttributes (1c white) - V6: 0 m; V7: 0 m; V8: 0 m; V9: 0; Programmversion: 2.2; Bezeichnung: 1c white; Plugin_Bezeichnung: MainObject; Plugin_Objektname: SmartPartCompressed; Version: 1.0; Allright_Bauteil_ID: 0452Mak0000000025; Abrechnungsart: St; Objektname: Dachflächenfenstermakro
1c white | Architektur (TB 450-459) | 0.55 | 0.4 | SKYLIGHT | AllplanAttributes (1c white) - V6: 0 m; V7: 0 m; V8: 0 m; V9: 0; Programmversion: 2.2; Bezeichnung: 1c white; Plugin_Bezeichnung: MainObject; Plugin_Objektname: SmartPartCompressed; Version: 1.0; Allright_Bauteil_ID: 0452Mak0000000020; Abrechnungsart: St; Objektname: Dachflächenfenstermakro

# IfcWindow: Window
In: Architektur (TB 200-209)
Type - PredefinedType: WINDOW; PartitioningType: DOUBLE_PANEL_VERTICAL; ParameterTakesPrecedence: no
Type - IfcWindowLiningProperties - LiningDepth: 0.05 m; LiningThickness: 0.03 m
OverallHeight: 0.5 m; OverallWidth: 0.51244 m
AllplanAttributes (Window) - V6: 0 m; V7: 0 m; V8: 0 m; V9: 0; Programmversion: 3.0; Bezeichnung: Window; Plugin_Bezeichnung: MainObject; Plugin_Objektname: SmartPartCompressed; Glasanteil_berücksichtigen: 100; Version: 8.0; Attributset-Objekt: Window; Allright_Bauteil_ID: 0200Mak0000156492; Abrechnungsart: St; Objektname: Fenstermakro, -SmartPart
AllplanQuantities - GlassSurface: 0; HeightWindowSillOutside: 0; HeightWindowSillInside: 0; OffsetOpeningBottom: 0; OffsetOpeningTop: 0; OffsetOpeningLeft: 0; OffsetOpeningRight: 0; DeductionOpeningBottom: 30; DeductionOpeningLeft: 30; DeductionOpeningRight: 30; DeductionOpeningTop: 30
Pset_WindowCommon - Status: NEW; IsExternal: no; ThermalTransmittance: 0 W/K/m2; SmokeStop: no; FireExit: no; Infiltration: 0 m3/hour/m; HasDrive: yes; HasSillExternal: yes; HasSillInternal: yes
